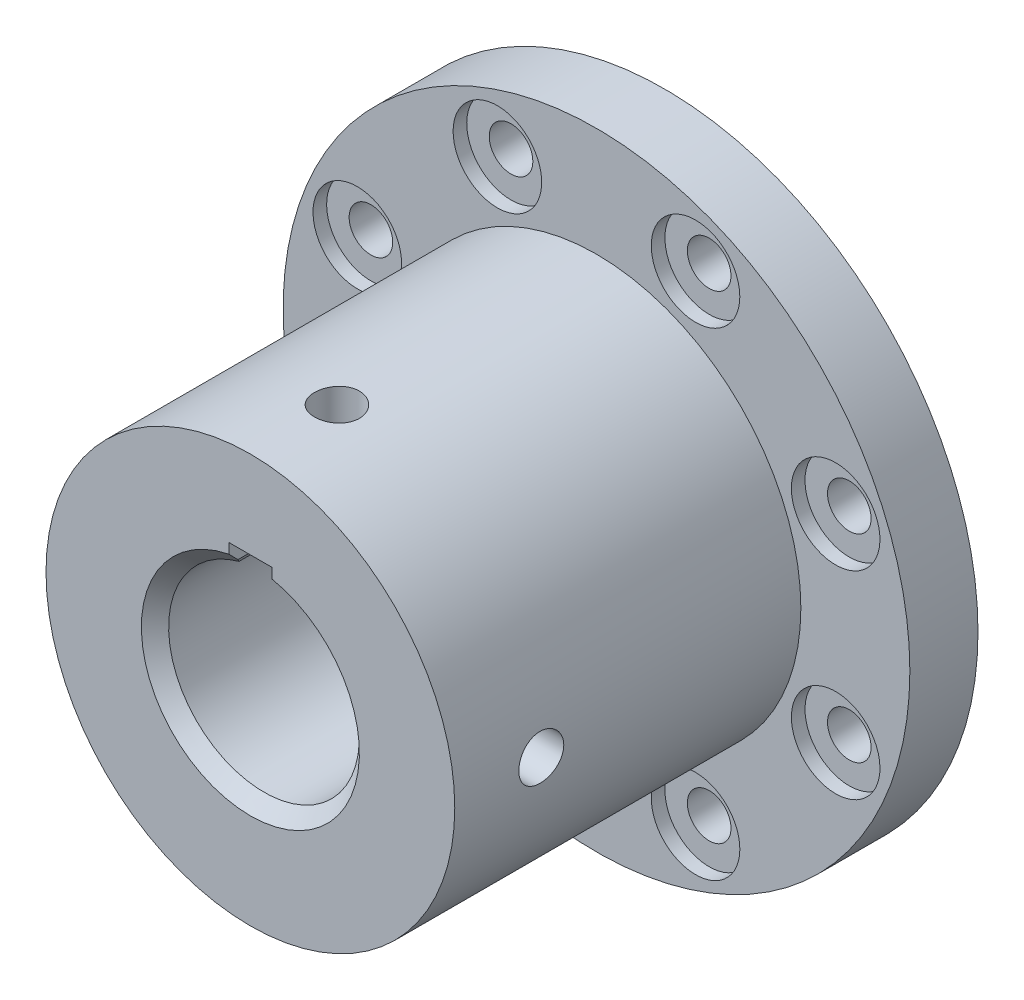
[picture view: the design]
ISO-10303-21;
HEADER;
FILE_DESCRIPTION(('STEP AP214'),'2;1');
FILE_NAME('part.step','',(''),(''),'','','');
FILE_SCHEMA(('AUTOMOTIVE_DESIGN { 1 0 10303 214 1 1 1 1 }'));
ENDSEC;
DATA;
#1=APPLICATION_CONTEXT('core data for automotive mechanical design processes');
#2=APPLICATION_PROTOCOL_DEFINITION('international standard','automotive_design',2000,#1);
#3=PRODUCT_CONTEXT('',#1,'mechanical');
#4=PRODUCT('Part','Part','',(#3));
#5=PRODUCT_RELATED_PRODUCT_CATEGORY('part','',(#4));
#6=PRODUCT_DEFINITION_FORMATION('','',#4);
#7=PRODUCT_DEFINITION_CONTEXT('part definition',#1,'design');
#8=PRODUCT_DEFINITION('design','',#6,#7);
#9=PRODUCT_DEFINITION_SHAPE('','',#8);
#10=(LENGTH_UNIT() NAMED_UNIT(*) SI_UNIT(.MILLI.,.METRE.));
#11=(NAMED_UNIT(*) PLANE_ANGLE_UNIT() SI_UNIT($,.RADIAN.));
#12=(NAMED_UNIT(*) SI_UNIT($,.STERADIAN.) SOLID_ANGLE_UNIT());
#13=UNCERTAINTY_MEASURE_WITH_UNIT(LENGTH_MEASURE(1.E-05),#10,'distance_accuracy_value','');
#14=(GEOMETRIC_REPRESENTATION_CONTEXT(3) GLOBAL_UNCERTAINTY_ASSIGNED_CONTEXT((#13)) GLOBAL_UNIT_ASSIGNED_CONTEXT((#10,
#11,#12)) REPRESENTATION_CONTEXT('',''));
#15=CARTESIAN_POINT('',(0.,0.,0.));
#16=DIRECTION('',(0.,0.,1.));
#17=DIRECTION('',(1.,0.,0.));
#18=AXIS2_PLACEMENT_3D('',#15,#16,#17);
#19=CARTESIAN_POINT('',(0.,0.,5.));
#20=DIRECTION('',(0.,0.,1.));
#21=DIRECTION('',(1.,0.,0.));
#22=AXIS2_PLACEMENT_3D('',#19,#20,#21);
#23=PLANE('',#22);
#24=CARTESIAN_POINT('',(-7.27197040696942,17.5533030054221,5.));
#25=DIRECTION('',(0.,0.,1.));
#26=DIRECTION('',(0.707106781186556,0.707106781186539,0.));
#27=AXIS2_PLACEMENT_3D('',#24,#25,#26);
#28=CIRCLE('',#27,3.25);
#29=CARTESIAN_POINT('',(-4.97387336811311,19.8514000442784,5.));
#30=VERTEX_POINT('',#29);
#31=EDGE_CURVE('E416',#30,#30,#28,.T.);
#32=ORIENTED_EDGE('',*,*,#31,.F.);
#33=EDGE_LOOP('',(#32));
#34=FACE_BOUND('',#33,.T.);
#35=CARTESIAN_POINT('',(-17.5541191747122,7.27000000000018,5.));
#36=DIRECTION('',(0.,0.,1.));
#37=DIRECTION('',(0.,1.,0.));
#38=AXIS2_PLACEMENT_3D('',#35,#36,#37);
#39=CIRCLE('',#38,3.25);
#40=CARTESIAN_POINT('',(-17.5541191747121,10.5200000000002,5.));
#41=VERTEX_POINT('',#40);
#42=EDGE_CURVE('E420',#41,#41,#39,.T.);
#43=ORIENTED_EDGE('',*,*,#42,.F.);
#44=EDGE_LOOP('',(#43));
#45=FACE_BOUND('',#44,.T.);
#46=CARTESIAN_POINT('',(-17.5533030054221,-7.27197040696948,5.));
#47=DIRECTION('',(0.,0.,1.));
#48=DIRECTION('',(-0.707106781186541,0.707106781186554,0.));
#49=AXIS2_PLACEMENT_3D('',#46,#47,#48);
#50=CIRCLE('',#49,3.25);
#51=CARTESIAN_POINT('',(-19.8514000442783,-4.97387336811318,5.));
#52=VERTEX_POINT('',#51);
#53=EDGE_CURVE('E424',#52,#52,#50,.T.);
#54=ORIENTED_EDGE('',*,*,#53,.F.);
#55=EDGE_LOOP('',(#54));
#56=FACE_BOUND('',#55,.T.);
#57=CARTESIAN_POINT('',(-7.27,-17.5541191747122,5.));
#58=DIRECTION('',(0.,0.,1.));
#59=DIRECTION('',(-1.,0.,0.));
#60=AXIS2_PLACEMENT_3D('',#57,#58,#59);
#61=CIRCLE('',#60,3.25);
#62=CARTESIAN_POINT('',(-10.52,-17.5541191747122,5.));
#63=VERTEX_POINT('',#62);
#64=EDGE_CURVE('E428',#63,#63,#61,.T.);
#65=ORIENTED_EDGE('',*,*,#64,.F.);
#66=EDGE_LOOP('',(#65));
#67=FACE_BOUND('',#66,.T.);
#68=CARTESIAN_POINT('',(7.27197040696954,-17.5533030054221,5.));
#69=DIRECTION('',(0.,0.,1.));
#70=DIRECTION('',(-0.707106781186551,-0.707106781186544,0.));
#71=AXIS2_PLACEMENT_3D('',#68,#69,#70);
#72=CIRCLE('',#71,3.25);
#73=CARTESIAN_POINT('',(4.97387336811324,-19.8514000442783,5.));
#74=VERTEX_POINT('',#73);
#75=EDGE_CURVE('E432',#74,#74,#72,.T.);
#76=ORIENTED_EDGE('',*,*,#75,.F.);
#77=EDGE_LOOP('',(#76));
#78=FACE_BOUND('',#77,.T.);
#79=CARTESIAN_POINT('',(17.5541191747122,-7.27000000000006,5.));
#80=DIRECTION('',(0.,0.,1.));
#81=DIRECTION('',(0.,-1.,0.));
#82=AXIS2_PLACEMENT_3D('',#79,#80,#81);
#83=CIRCLE('',#82,3.25);
#84=CARTESIAN_POINT('',(17.5541191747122,-10.5200000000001,5.));
#85=VERTEX_POINT('',#84);
#86=EDGE_CURVE('E436',#85,#85,#83,.T.);
#87=ORIENTED_EDGE('',*,*,#86,.F.);
#88=EDGE_LOOP('',(#87));
#89=FACE_BOUND('',#88,.T.);
#90=CARTESIAN_POINT('',(17.553303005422,7.2719704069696,5.));
#91=DIRECTION('',(0.,0.,1.));
#92=DIRECTION('',(0.707106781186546,-0.707106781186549,0.));
#93=AXIS2_PLACEMENT_3D('',#90,#91,#92);
#94=CIRCLE('',#93,3.25);
#95=CARTESIAN_POINT('',(19.8514000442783,4.97387336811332,5.));
#96=VERTEX_POINT('',#95);
#97=EDGE_CURVE('E440',#96,#96,#94,.T.);
#98=ORIENTED_EDGE('',*,*,#97,.F.);
#99=EDGE_LOOP('',(#98));
#100=FACE_BOUND('',#99,.T.);
#101=CARTESIAN_POINT('',(7.27,17.5541191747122,5.));
#102=DIRECTION('',(0.,0.,1.));
#103=DIRECTION('',(1.,0.,0.));
#104=AXIS2_PLACEMENT_3D('',#101,#102,#103);
#105=CIRCLE('',#104,3.25);
#106=CARTESIAN_POINT('',(10.52,17.5541191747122,5.));
#107=VERTEX_POINT('',#106);
#108=EDGE_CURVE('E444',#107,#107,#105,.T.);
#109=ORIENTED_EDGE('',*,*,#108,.F.);
#110=EDGE_LOOP('',(#109));
#111=FACE_BOUND('',#110,.T.);
#112=CARTESIAN_POINT('',(0.,0.,5.));
#113=DIRECTION('',(0.,0.,1.));
#114=DIRECTION('',(1.,0.,0.));
#115=AXIS2_PLACEMENT_3D('',#112,#113,#114);
#116=CIRCLE('',#115,23.);
#117=CARTESIAN_POINT('',(23.,0.,5.));
#118=VERTEX_POINT('',#117);
#119=EDGE_CURVE('E448',#118,#118,#116,.T.);
#120=ORIENTED_EDGE('',*,*,#119,.T.);
#121=EDGE_LOOP('',(#120));
#122=FACE_BOUND('',#121,.T.);
#123=CARTESIAN_POINT('',(0.,0.,5.));
#124=DIRECTION('',(0.,0.,1.));
#125=DIRECTION('',(1.,0.,0.));
#126=AXIS2_PLACEMENT_3D('',#123,#124,#125);
#127=CIRCLE('',#126,15.);
#128=CARTESIAN_POINT('',(15.,0.,5.));
#129=VERTEX_POINT('',#128);
#130=EDGE_CURVE('E289',#129,#129,#127,.T.);
#131=ORIENTED_EDGE('',*,*,#130,.F.);
#132=EDGE_LOOP('',(#131));
#133=FACE_BOUND('',#132,.T.);
#134=ADVANCED_FACE('F34',(#34,#45,#56,#67,#78,#89,#100,#111,#122,#133),#23,.T.);
#135=CARTESIAN_POINT('',(-7.27197040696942,17.5533030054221,5.));
#136=DIRECTION('',(0.,0.,1.));
#137=DIRECTION('',(1.,0.,0.));
#138=AXIS2_PLACEMENT_3D('',#135,#136,#137);
#139=CYLINDRICAL_SURFACE('',#138,1.6);
#140=CARTESIAN_POINT('',(-7.27197040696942,17.5533030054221,0.));
#141=DIRECTION('',(0.,0.,1.));
#142=DIRECTION('',(1.,0.,0.));
#143=AXIS2_PLACEMENT_3D('',#140,#141,#142);
#144=CIRCLE('',#143,1.6);
#145=CARTESIAN_POINT('',(-5.67197040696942,17.5533030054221,0.));
#146=VERTEX_POINT('',#145);
#147=EDGE_CURVE('E489',#146,#146,#144,.T.);
#148=ORIENTED_EDGE('',*,*,#147,.F.);
#149=EDGE_LOOP('',(#148));
#150=FACE_BOUND('',#149,.T.);
#151=CARTESIAN_POINT('',(-7.27197040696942,17.5533030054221,4.));
#152=DIRECTION('',(0.,0.,1.));
#153=DIRECTION('',(1.,0.,0.));
#154=AXIS2_PLACEMENT_3D('',#151,#152,#153);
#155=CIRCLE('',#154,1.6);
#156=CARTESIAN_POINT('',(-5.67197040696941,17.5533030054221,4.));
#157=VERTEX_POINT('',#156);
#158=EDGE_CURVE('E457',#157,#157,#155,.F.);
#159=ORIENTED_EDGE('',*,*,#158,.F.);
#160=EDGE_LOOP('',(#159));
#161=FACE_BOUND('',#160,.T.);
#162=ADVANCED_FACE('F356',(#150,#161),#139,.F.);
#163=CARTESIAN_POINT('',(-17.5541191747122,7.27000000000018,5.));
#164=DIRECTION('',(0.,0.,1.));
#165=DIRECTION('',(1.,0.,0.));
#166=AXIS2_PLACEMENT_3D('',#163,#164,#165);
#167=CYLINDRICAL_SURFACE('',#166,1.6);
#168=CARTESIAN_POINT('',(-17.5541191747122,7.27000000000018,0.));
#169=DIRECTION('',(0.,0.,1.));
#170=DIRECTION('',(1.,0.,0.));
#171=AXIS2_PLACEMENT_3D('',#168,#169,#170);
#172=CIRCLE('',#171,1.6);
#173=CARTESIAN_POINT('',(-15.9541191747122,7.27000000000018,0.));
#174=VERTEX_POINT('',#173);
#175=EDGE_CURVE('E491',#174,#174,#172,.T.);
#176=ORIENTED_EDGE('',*,*,#175,.F.);
#177=EDGE_LOOP('',(#176));
#178=FACE_BOUND('',#177,.T.);
#179=CARTESIAN_POINT('',(-17.5541191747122,7.27000000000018,4.));
#180=DIRECTION('',(0.,0.,1.));
#181=DIRECTION('',(1.,0.,0.));
#182=AXIS2_PLACEMENT_3D('',#179,#180,#181);
#183=CIRCLE('',#182,1.6);
#184=CARTESIAN_POINT('',(-15.9541191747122,7.27000000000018,4.));
#185=VERTEX_POINT('',#184);
#186=EDGE_CURVE('E462',#185,#185,#183,.F.);
#187=ORIENTED_EDGE('',*,*,#186,.F.);
#188=EDGE_LOOP('',(#187));
#189=FACE_BOUND('',#188,.T.);
#190=ADVANCED_FACE('F359',(#178,#189),#167,.F.);
#191=CARTESIAN_POINT('',(-17.5533030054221,-7.27197040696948,5.));
#192=DIRECTION('',(0.,0.,1.));
#193=DIRECTION('',(1.,0.,0.));
#194=AXIS2_PLACEMENT_3D('',#191,#192,#193);
#195=CYLINDRICAL_SURFACE('',#194,1.6);
#196=CARTESIAN_POINT('',(-17.5533030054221,-7.27197040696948,0.));
#197=DIRECTION('',(0.,0.,1.));
#198=DIRECTION('',(1.,0.,0.));
#199=AXIS2_PLACEMENT_3D('',#196,#197,#198);
#200=CIRCLE('',#199,1.6);
#201=CARTESIAN_POINT('',(-15.9533030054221,-7.27197040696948,0.));
#202=VERTEX_POINT('',#201);
#203=EDGE_CURVE('E494',#202,#202,#200,.T.);
#204=ORIENTED_EDGE('',*,*,#203,.F.);
#205=EDGE_LOOP('',(#204));
#206=FACE_BOUND('',#205,.T.);
#207=CARTESIAN_POINT('',(-17.5533030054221,-7.27197040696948,4.));
#208=DIRECTION('',(0.,0.,1.));
#209=DIRECTION('',(1.,0.,0.));
#210=AXIS2_PLACEMENT_3D('',#207,#208,#209);
#211=CIRCLE('',#210,1.6);
#212=CARTESIAN_POINT('',(-15.9533030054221,-7.27197040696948,4.));
#213=VERTEX_POINT('',#212);
#214=EDGE_CURVE('E467',#213,#213,#211,.F.);
#215=ORIENTED_EDGE('',*,*,#214,.F.);
#216=EDGE_LOOP('',(#215));
#217=FACE_BOUND('',#216,.T.);
#218=ADVANCED_FACE('F363',(#206,#217),#195,.F.);
#219=CARTESIAN_POINT('',(-7.27,-17.5541191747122,5.));
#220=DIRECTION('',(0.,0.,1.));
#221=DIRECTION('',(1.,0.,0.));
#222=AXIS2_PLACEMENT_3D('',#219,#220,#221);
#223=CYLINDRICAL_SURFACE('',#222,1.6);
#224=CARTESIAN_POINT('',(-7.27,-17.5541191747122,0.));
#225=DIRECTION('',(0.,0.,1.));
#226=DIRECTION('',(1.,0.,0.));
#227=AXIS2_PLACEMENT_3D('',#224,#225,#226);
#228=CIRCLE('',#227,1.6);
#229=CARTESIAN_POINT('',(-5.67,-17.5541191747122,0.));
#230=VERTEX_POINT('',#229);
#231=EDGE_CURVE('E497',#230,#230,#228,.T.);
#232=ORIENTED_EDGE('',*,*,#231,.F.);
#233=EDGE_LOOP('',(#232));
#234=FACE_BOUND('',#233,.T.);
#235=CARTESIAN_POINT('',(-7.27,-17.5541191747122,4.));
#236=DIRECTION('',(0.,0.,1.));
#237=DIRECTION('',(1.,0.,0.));
#238=AXIS2_PLACEMENT_3D('',#235,#236,#237);
#239=CIRCLE('',#238,1.6);
#240=CARTESIAN_POINT('',(-5.67,-17.5541191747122,4.));
#241=VERTEX_POINT('',#240);
#242=EDGE_CURVE('E472',#241,#241,#239,.F.);
#243=ORIENTED_EDGE('',*,*,#242,.F.);
#244=EDGE_LOOP('',(#243));
#245=FACE_BOUND('',#244,.T.);
#246=ADVANCED_FACE('F367',(#234,#245),#223,.F.);
#247=CARTESIAN_POINT('',(7.27197040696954,-17.5533030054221,5.));
#248=DIRECTION('',(0.,0.,1.));
#249=DIRECTION('',(1.,0.,0.));
#250=AXIS2_PLACEMENT_3D('',#247,#248,#249);
#251=CYLINDRICAL_SURFACE('',#250,1.6);
#252=CARTESIAN_POINT('',(7.27197040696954,-17.5533030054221,0.));
#253=DIRECTION('',(0.,0.,1.));
#254=DIRECTION('',(1.,0.,0.));
#255=AXIS2_PLACEMENT_3D('',#252,#253,#254);
#256=CIRCLE('',#255,1.6);
#257=CARTESIAN_POINT('',(8.87197040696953,-17.5533030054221,0.));
#258=VERTEX_POINT('',#257);
#259=EDGE_CURVE('E500',#258,#258,#256,.T.);
#260=ORIENTED_EDGE('',*,*,#259,.F.);
#261=EDGE_LOOP('',(#260));
#262=FACE_BOUND('',#261,.T.);
#263=CARTESIAN_POINT('',(7.27197040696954,-17.5533030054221,4.));
#264=DIRECTION('',(0.,0.,1.));
#265=DIRECTION('',(1.,0.,0.));
#266=AXIS2_PLACEMENT_3D('',#263,#264,#265);
#267=CIRCLE('',#266,1.6);
#268=CARTESIAN_POINT('',(8.87197040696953,-17.5533030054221,4.));
#269=VERTEX_POINT('',#268);
#270=EDGE_CURVE('E477',#269,#269,#267,.F.);
#271=ORIENTED_EDGE('',*,*,#270,.F.);
#272=EDGE_LOOP('',(#271));
#273=FACE_BOUND('',#272,.T.);
#274=ADVANCED_FACE('F371',(#262,#273),#251,.F.);
#275=CARTESIAN_POINT('',(17.5541191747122,-7.27000000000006,5.));
#276=DIRECTION('',(0.,0.,1.));
#277=DIRECTION('',(1.,0.,0.));
#278=AXIS2_PLACEMENT_3D('',#275,#276,#277);
#279=CYLINDRICAL_SURFACE('',#278,1.6);
#280=CARTESIAN_POINT('',(17.5541191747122,-7.27000000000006,0.));
#281=DIRECTION('',(0.,0.,1.));
#282=DIRECTION('',(1.,0.,0.));
#283=AXIS2_PLACEMENT_3D('',#280,#281,#282);
#284=CIRCLE('',#283,1.6);
#285=CARTESIAN_POINT('',(19.1541191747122,-7.27000000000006,0.));
#286=VERTEX_POINT('',#285);
#287=EDGE_CURVE('E503',#286,#286,#284,.T.);
#288=ORIENTED_EDGE('',*,*,#287,.F.);
#289=EDGE_LOOP('',(#288));
#290=FACE_BOUND('',#289,.T.);
#291=CARTESIAN_POINT('',(17.5541191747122,-7.27000000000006,4.));
#292=DIRECTION('',(0.,0.,1.));
#293=DIRECTION('',(1.,0.,0.));
#294=AXIS2_PLACEMENT_3D('',#291,#292,#293);
#295=CIRCLE('',#294,1.6);
#296=CARTESIAN_POINT('',(19.1541191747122,-7.27000000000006,4.));
#297=VERTEX_POINT('',#296);
#298=EDGE_CURVE('E482',#297,#297,#295,.F.);
#299=ORIENTED_EDGE('',*,*,#298,.F.);
#300=EDGE_LOOP('',(#299));
#301=FACE_BOUND('',#300,.T.);
#302=ADVANCED_FACE('F375',(#290,#301),#279,.F.);
#303=CARTESIAN_POINT('',(17.553303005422,7.2719704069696,5.));
#304=DIRECTION('',(0.,0.,1.));
#305=DIRECTION('',(1.,0.,0.));
#306=AXIS2_PLACEMENT_3D('',#303,#304,#305);
#307=CYLINDRICAL_SURFACE('',#306,1.6);
#308=CARTESIAN_POINT('',(17.553303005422,7.2719704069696,0.));
#309=DIRECTION('',(0.,0.,1.));
#310=DIRECTION('',(1.,0.,0.));
#311=AXIS2_PLACEMENT_3D('',#308,#309,#310);
#312=CIRCLE('',#311,1.6);
#313=CARTESIAN_POINT('',(19.153303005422,7.2719704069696,0.));
#314=VERTEX_POINT('',#313);
#315=EDGE_CURVE('E506',#314,#314,#312,.T.);
#316=ORIENTED_EDGE('',*,*,#315,.F.);
#317=EDGE_LOOP('',(#316));
#318=FACE_BOUND('',#317,.T.);
#319=CARTESIAN_POINT('',(17.553303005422,7.2719704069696,4.));
#320=DIRECTION('',(0.,0.,1.));
#321=DIRECTION('',(1.,0.,0.));
#322=AXIS2_PLACEMENT_3D('',#319,#320,#321);
#323=CIRCLE('',#322,1.6);
#324=CARTESIAN_POINT('',(19.153303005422,7.2719704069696,4.));
#325=VERTEX_POINT('',#324);
#326=EDGE_CURVE('E487',#325,#325,#323,.F.);
#327=ORIENTED_EDGE('',*,*,#326,.F.);
#328=EDGE_LOOP('',(#327));
#329=FACE_BOUND('',#328,.T.);
#330=ADVANCED_FACE('F379',(#318,#329),#307,.F.);
#331=CARTESIAN_POINT('',(7.27,17.5541191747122,5.));
#332=DIRECTION('',(0.,0.,1.));
#333=DIRECTION('',(1.,0.,0.));
#334=AXIS2_PLACEMENT_3D('',#331,#332,#333);
#335=CYLINDRICAL_SURFACE('',#334,1.6);
#336=CARTESIAN_POINT('',(7.27,17.5541191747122,0.));
#337=DIRECTION('',(0.,0.,1.));
#338=DIRECTION('',(1.,0.,0.));
#339=AXIS2_PLACEMENT_3D('',#336,#337,#338);
#340=CIRCLE('',#339,1.6);
#341=CARTESIAN_POINT('',(8.87,17.5541191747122,0.));
#342=VERTEX_POINT('',#341);
#343=EDGE_CURVE('E514',#342,#342,#340,.T.);
#344=ORIENTED_EDGE('',*,*,#343,.F.);
#345=EDGE_LOOP('',(#344));
#346=FACE_BOUND('',#345,.T.);
#347=CARTESIAN_POINT('',(7.27,17.5541191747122,4.));
#348=DIRECTION('',(0.,0.,1.));
#349=DIRECTION('',(1.,0.,0.));
#350=AXIS2_PLACEMENT_3D('',#347,#348,#349);
#351=CIRCLE('',#350,1.6);
#352=CARTESIAN_POINT('',(8.87,17.5541191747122,4.));
#353=VERTEX_POINT('',#352);
#354=EDGE_CURVE('E512',#353,#353,#351,.F.);
#355=ORIENTED_EDGE('',*,*,#354,.F.);
#356=EDGE_LOOP('',(#355));
#357=FACE_BOUND('',#356,.T.);
#358=ADVANCED_FACE('F383',(#346,#357),#335,.F.);
#359=CARTESIAN_POINT('',(0.,0.,5.));
#360=DIRECTION('',(0.,0.,-1.));
#361=DIRECTION('',(-1.,0.,0.));
#362=AXIS2_PLACEMENT_3D('',#359,#360,#361);
#363=CYLINDRICAL_SURFACE('',#362,23.);
#364=ORIENTED_EDGE('',*,*,#119,.F.);
#365=EDGE_LOOP('',(#364));
#366=FACE_BOUND('',#365,.T.);
#367=CARTESIAN_POINT('',(0.,0.,0.));
#368=DIRECTION('',(0.,0.,1.));
#369=DIRECTION('',(1.,0.,0.));
#370=AXIS2_PLACEMENT_3D('',#367,#368,#369);
#371=CIRCLE('',#370,23.);
#372=CARTESIAN_POINT('',(23.,0.,0.));
#373=VERTEX_POINT('',#372);
#374=EDGE_CURVE('E521',#373,#373,#371,.T.);
#375=ORIENTED_EDGE('',*,*,#374,.T.);
#376=EDGE_LOOP('',(#375));
#377=FACE_BOUND('',#376,.T.);
#378=ADVANCED_FACE('F218',(#366,#377),#363,.T.);
#379=CARTESIAN_POINT('',(0.,0.,5.));
#380=DIRECTION('',(0.,0.,1.));
#381=DIRECTION('',(1.,0.,0.));
#382=AXIS2_PLACEMENT_3D('',#379,#380,#381);
#383=CIRCLE('',#382,7.);
#384=CARTESIAN_POINT('',(7.,0.,5.));
#385=VERTEX_POINT('',#384);
#386=EDGE_CURVE('E525',#385,#385,#383,.F.);
#387=ORIENTED_EDGE('',*,*,#386,.F.);
#388=EDGE_LOOP('',(#387));
#389=FACE_BOUND('',#388,.T.);
#390=CARTESIAN_POINT('',(0.,0.,5.));
#391=DIRECTION('',(0.,0.,1.));
#392=DIRECTION('',(1.,0.,0.));
#393=AXIS2_PLACEMENT_3D('',#390,#391,#392);
#394=CIRCLE('',#393,2.);
#395=CARTESIAN_POINT('',(2.,0.,5.));
#396=VERTEX_POINT('',#395);
#397=EDGE_CURVE('E517',#396,#396,#394,.T.);
#398=ORIENTED_EDGE('',*,*,#397,.F.);
#399=EDGE_LOOP('',(#398));
#400=FACE_BOUND('',#399,.T.);
#401=ADVANCED_FACE('F400',(#389,#400),#23,.T.);
#402=CARTESIAN_POINT('',(0.,0.,0.));
#403=DIRECTION('',(0.,0.,1.));
#404=DIRECTION('',(1.,0.,0.));
#405=AXIS2_PLACEMENT_3D('',#402,#403,#404);
#406=PLANE('',#405);
#407=ORIENTED_EDGE('',*,*,#147,.T.);
#408=EDGE_LOOP('',(#407));
#409=FACE_BOUND('',#408,.T.);
#410=ORIENTED_EDGE('',*,*,#175,.T.);
#411=EDGE_LOOP('',(#410));
#412=FACE_BOUND('',#411,.T.);
#413=ORIENTED_EDGE('',*,*,#203,.T.);
#414=EDGE_LOOP('',(#413));
#415=FACE_BOUND('',#414,.T.);
#416=ORIENTED_EDGE('',*,*,#231,.T.);
#417=EDGE_LOOP('',(#416));
#418=FACE_BOUND('',#417,.T.);
#419=ORIENTED_EDGE('',*,*,#259,.T.);
#420=EDGE_LOOP('',(#419));
#421=FACE_BOUND('',#420,.T.);
#422=ORIENTED_EDGE('',*,*,#287,.T.);
#423=EDGE_LOOP('',(#422));
#424=FACE_BOUND('',#423,.T.);
#425=ORIENTED_EDGE('',*,*,#315,.T.);
#426=EDGE_LOOP('',(#425));
#427=FACE_BOUND('',#426,.T.);
#428=ORIENTED_EDGE('',*,*,#343,.T.);
#429=EDGE_LOOP('',(#428));
#430=FACE_BOUND('',#429,.T.);
#431=CARTESIAN_POINT('',(0.,0.,0.));
#432=DIRECTION('',(0.,0.,1.));
#433=DIRECTION('',(1.,0.,0.));
#434=AXIS2_PLACEMENT_3D('',#431,#432,#433);
#435=CIRCLE('',#434,2.);
#436=CARTESIAN_POINT('',(2.,0.,0.));
#437=VERTEX_POINT('',#436);
#438=EDGE_CURVE('E518',#437,#437,#435,.T.);
#439=ORIENTED_EDGE('',*,*,#438,.T.);
#440=EDGE_LOOP('',(#439));
#441=FACE_BOUND('',#440,.T.);
#442=ORIENTED_EDGE('',*,*,#374,.F.);
#443=EDGE_LOOP('',(#442));
#444=FACE_BOUND('',#443,.T.);
#445=ADVANCED_FACE('F398',(#409,#412,#415,#418,#421,#424,#427,#430,#441,#444),#406,.F.);
#446=CARTESIAN_POINT('',(0.,0.,0.));
#447=DIRECTION('',(0.,0.,1.));
#448=DIRECTION('',(1.,0.,0.));
#449=AXIS2_PLACEMENT_3D('',#446,#447,#448);
#450=CYLINDRICAL_SURFACE('',#449,2.);
#451=ORIENTED_EDGE('',*,*,#438,.F.);
#452=EDGE_LOOP('',(#451));
#453=FACE_BOUND('',#452,.T.);
#454=ORIENTED_EDGE('',*,*,#397,.T.);
#455=EDGE_LOOP('',(#454));
#456=FACE_BOUND('',#455,.T.);
#457=ADVANCED_FACE('F388',(#453,#456),#450,.F.);
#458=CARTESIAN_POINT('',(7.27,17.5541191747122,4.));
#459=DIRECTION('',(0.,0.,1.));
#460=DIRECTION('',(1.,0.,0.));
#461=AXIS2_PLACEMENT_3D('',#458,#459,#460);
#462=PLANE('',#461);
#463=CARTESIAN_POINT('',(7.27,17.5541191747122,4.));
#464=DIRECTION('',(0.,0.,1.));
#465=DIRECTION('',(1.,0.,0.));
#466=AXIS2_PLACEMENT_3D('',#463,#464,#465);
#467=CIRCLE('',#466,3.25);
#468=CARTESIAN_POINT('',(10.52,17.5541191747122,4.));
#469=VERTEX_POINT('',#468);
#470=EDGE_CURVE('E509',#469,#469,#467,.T.);
#471=ORIENTED_EDGE('',*,*,#470,.T.);
#472=EDGE_LOOP('',(#471));
#473=FACE_BOUND('',#472,.T.);
#474=ORIENTED_EDGE('',*,*,#354,.T.);
#475=EDGE_LOOP('',(#474));
#476=FACE_BOUND('',#475,.T.);
#477=ADVANCED_FACE('F385',(#473,#476),#462,.T.);
#478=CARTESIAN_POINT('',(7.27,17.5541191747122,4.));
#479=DIRECTION('',(0.,0.,1.));
#480=DIRECTION('',(1.,0.,0.));
#481=AXIS2_PLACEMENT_3D('',#478,#479,#480);
#482=CYLINDRICAL_SURFACE('',#481,3.25);
#483=ORIENTED_EDGE('',*,*,#470,.F.);
#484=EDGE_LOOP('',(#483));
#485=FACE_BOUND('',#484,.T.);
#486=ORIENTED_EDGE('',*,*,#108,.T.);
#487=EDGE_LOOP('',(#486));
#488=FACE_BOUND('',#487,.T.);
#489=ADVANCED_FACE('F351',(#485,#488),#482,.F.);
#490=CARTESIAN_POINT('',(17.553303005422,7.2719704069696,4.));
#491=DIRECTION('',(0.,0.,1.));
#492=DIRECTION('',(0.707106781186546,-0.707106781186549,0.));
#493=AXIS2_PLACEMENT_3D('',#490,#491,#492);
#494=PLANE('',#493);
#495=CARTESIAN_POINT('',(17.553303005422,7.2719704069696,4.));
#496=DIRECTION('',(0.,0.,1.));
#497=DIRECTION('',(0.707106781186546,-0.707106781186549,0.));
#498=AXIS2_PLACEMENT_3D('',#495,#496,#497);
#499=CIRCLE('',#498,3.25);
#500=CARTESIAN_POINT('',(19.8514000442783,4.97387336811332,4.));
#501=VERTEX_POINT('',#500);
#502=EDGE_CURVE('E484',#501,#501,#499,.T.);
#503=ORIENTED_EDGE('',*,*,#502,.T.);
#504=EDGE_LOOP('',(#503));
#505=FACE_BOUND('',#504,.T.);
#506=ORIENTED_EDGE('',*,*,#326,.T.);
#507=EDGE_LOOP('',(#506));
#508=FACE_BOUND('',#507,.T.);
#509=ADVANCED_FACE('F348',(#505,#508),#494,.T.);
#510=CARTESIAN_POINT('',(17.553303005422,7.2719704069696,4.));
#511=DIRECTION('',(0.,0.,1.));
#512=DIRECTION('',(1.,0.,0.));
#513=AXIS2_PLACEMENT_3D('',#510,#511,#512);
#514=CYLINDRICAL_SURFACE('',#513,3.25);
#515=ORIENTED_EDGE('',*,*,#502,.F.);
#516=EDGE_LOOP('',(#515));
#517=FACE_BOUND('',#516,.T.);
#518=ORIENTED_EDGE('',*,*,#97,.T.);
#519=EDGE_LOOP('',(#518));
#520=FACE_BOUND('',#519,.T.);
#521=ADVANCED_FACE('F343',(#517,#520),#514,.F.);
#522=CARTESIAN_POINT('',(17.5541191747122,-7.27000000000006,4.));
#523=DIRECTION('',(0.,0.,1.));
#524=DIRECTION('',(0.,-1.,0.));
#525=AXIS2_PLACEMENT_3D('',#522,#523,#524);
#526=PLANE('',#525);
#527=CARTESIAN_POINT('',(17.5541191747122,-7.27000000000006,4.));
#528=DIRECTION('',(0.,0.,1.));
#529=DIRECTION('',(0.,-1.,0.));
#530=AXIS2_PLACEMENT_3D('',#527,#528,#529);
#531=CIRCLE('',#530,3.25);
#532=CARTESIAN_POINT('',(17.5541191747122,-10.5200000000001,4.));
#533=VERTEX_POINT('',#532);
#534=EDGE_CURVE('E479',#533,#533,#531,.T.);
#535=ORIENTED_EDGE('',*,*,#534,.T.);
#536=EDGE_LOOP('',(#535));
#537=FACE_BOUND('',#536,.T.);
#538=ORIENTED_EDGE('',*,*,#298,.T.);
#539=EDGE_LOOP('',(#538));
#540=FACE_BOUND('',#539,.T.);
#541=ADVANCED_FACE('F340',(#537,#540),#526,.T.);
#542=CARTESIAN_POINT('',(17.5541191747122,-7.27000000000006,4.));
#543=DIRECTION('',(0.,0.,1.));
#544=DIRECTION('',(1.,0.,0.));
#545=AXIS2_PLACEMENT_3D('',#542,#543,#544);
#546=CYLINDRICAL_SURFACE('',#545,3.25);
#547=ORIENTED_EDGE('',*,*,#534,.F.);
#548=EDGE_LOOP('',(#547));
#549=FACE_BOUND('',#548,.T.);
#550=ORIENTED_EDGE('',*,*,#86,.T.);
#551=EDGE_LOOP('',(#550));
#552=FACE_BOUND('',#551,.T.);
#553=ADVANCED_FACE('F335',(#549,#552),#546,.F.);
#554=CARTESIAN_POINT('',(7.27197040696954,-17.5533030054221,4.));
#555=DIRECTION('',(0.,0.,1.));
#556=DIRECTION('',(-0.707106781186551,-0.707106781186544,0.));
#557=AXIS2_PLACEMENT_3D('',#554,#555,#556);
#558=PLANE('',#557);
#559=CARTESIAN_POINT('',(7.27197040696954,-17.5533030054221,4.));
#560=DIRECTION('',(0.,0.,1.));
#561=DIRECTION('',(-0.707106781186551,-0.707106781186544,0.));
#562=AXIS2_PLACEMENT_3D('',#559,#560,#561);
#563=CIRCLE('',#562,3.25);
#564=CARTESIAN_POINT('',(4.97387336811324,-19.8514000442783,4.));
#565=VERTEX_POINT('',#564);
#566=EDGE_CURVE('E474',#565,#565,#563,.T.);
#567=ORIENTED_EDGE('',*,*,#566,.T.);
#568=EDGE_LOOP('',(#567));
#569=FACE_BOUND('',#568,.T.);
#570=ORIENTED_EDGE('',*,*,#270,.T.);
#571=EDGE_LOOP('',(#570));
#572=FACE_BOUND('',#571,.T.);
#573=ADVANCED_FACE('F332',(#569,#572),#558,.T.);
#574=CARTESIAN_POINT('',(7.27197040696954,-17.5533030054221,4.));
#575=DIRECTION('',(0.,0.,1.));
#576=DIRECTION('',(1.,0.,0.));
#577=AXIS2_PLACEMENT_3D('',#574,#575,#576);
#578=CYLINDRICAL_SURFACE('',#577,3.25);
#579=ORIENTED_EDGE('',*,*,#566,.F.);
#580=EDGE_LOOP('',(#579));
#581=FACE_BOUND('',#580,.T.);
#582=ORIENTED_EDGE('',*,*,#75,.T.);
#583=EDGE_LOOP('',(#582));
#584=FACE_BOUND('',#583,.T.);
#585=ADVANCED_FACE('F327',(#581,#584),#578,.F.);
#586=CARTESIAN_POINT('',(-7.27,-17.5541191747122,4.));
#587=DIRECTION('',(0.,0.,1.));
#588=DIRECTION('',(-1.,0.,0.));
#589=AXIS2_PLACEMENT_3D('',#586,#587,#588);
#590=PLANE('',#589);
#591=CARTESIAN_POINT('',(-7.27,-17.5541191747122,4.));
#592=DIRECTION('',(0.,0.,1.));
#593=DIRECTION('',(-1.,0.,0.));
#594=AXIS2_PLACEMENT_3D('',#591,#592,#593);
#595=CIRCLE('',#594,3.25);
#596=CARTESIAN_POINT('',(-10.52,-17.5541191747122,4.));
#597=VERTEX_POINT('',#596);
#598=EDGE_CURVE('E469',#597,#597,#595,.T.);
#599=ORIENTED_EDGE('',*,*,#598,.T.);
#600=EDGE_LOOP('',(#599));
#601=FACE_BOUND('',#600,.T.);
#602=ORIENTED_EDGE('',*,*,#242,.T.);
#603=EDGE_LOOP('',(#602));
#604=FACE_BOUND('',#603,.T.);
#605=ADVANCED_FACE('F324',(#601,#604),#590,.T.);
#606=CARTESIAN_POINT('',(-7.27,-17.5541191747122,4.));
#607=DIRECTION('',(0.,0.,1.));
#608=DIRECTION('',(1.,0.,0.));
#609=AXIS2_PLACEMENT_3D('',#606,#607,#608);
#610=CYLINDRICAL_SURFACE('',#609,3.25);
#611=ORIENTED_EDGE('',*,*,#598,.F.);
#612=EDGE_LOOP('',(#611));
#613=FACE_BOUND('',#612,.T.);
#614=ORIENTED_EDGE('',*,*,#64,.T.);
#615=EDGE_LOOP('',(#614));
#616=FACE_BOUND('',#615,.T.);
#617=ADVANCED_FACE('F319',(#613,#616),#610,.F.);
#618=CARTESIAN_POINT('',(-17.5533030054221,-7.27197040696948,4.));
#619=DIRECTION('',(0.,0.,1.));
#620=DIRECTION('',(-0.707106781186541,0.707106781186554,0.));
#621=AXIS2_PLACEMENT_3D('',#618,#619,#620);
#622=PLANE('',#621);
#623=CARTESIAN_POINT('',(-17.5533030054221,-7.27197040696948,4.));
#624=DIRECTION('',(0.,0.,1.));
#625=DIRECTION('',(-0.707106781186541,0.707106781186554,0.));
#626=AXIS2_PLACEMENT_3D('',#623,#624,#625);
#627=CIRCLE('',#626,3.25);
#628=CARTESIAN_POINT('',(-19.8514000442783,-4.97387336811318,4.));
#629=VERTEX_POINT('',#628);
#630=EDGE_CURVE('E464',#629,#629,#627,.T.);
#631=ORIENTED_EDGE('',*,*,#630,.T.);
#632=EDGE_LOOP('',(#631));
#633=FACE_BOUND('',#632,.T.);
#634=ORIENTED_EDGE('',*,*,#214,.T.);
#635=EDGE_LOOP('',(#634));
#636=FACE_BOUND('',#635,.T.);
#637=ADVANCED_FACE('F316',(#633,#636),#622,.T.);
#638=CARTESIAN_POINT('',(-17.5533030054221,-7.27197040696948,4.));
#639=DIRECTION('',(0.,0.,1.));
#640=DIRECTION('',(1.,0.,0.));
#641=AXIS2_PLACEMENT_3D('',#638,#639,#640);
#642=CYLINDRICAL_SURFACE('',#641,3.25);
#643=ORIENTED_EDGE('',*,*,#630,.F.);
#644=EDGE_LOOP('',(#643));
#645=FACE_BOUND('',#644,.T.);
#646=ORIENTED_EDGE('',*,*,#53,.T.);
#647=EDGE_LOOP('',(#646));
#648=FACE_BOUND('',#647,.T.);
#649=ADVANCED_FACE('F311',(#645,#648),#642,.F.);
#650=CARTESIAN_POINT('',(-17.5541191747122,7.27000000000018,4.));
#651=DIRECTION('',(0.,0.,1.));
#652=DIRECTION('',(0.,1.,0.));
#653=AXIS2_PLACEMENT_3D('',#650,#651,#652);
#654=PLANE('',#653);
#655=CARTESIAN_POINT('',(-17.5541191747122,7.27000000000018,4.));
#656=DIRECTION('',(0.,0.,1.));
#657=DIRECTION('',(0.,1.,0.));
#658=AXIS2_PLACEMENT_3D('',#655,#656,#657);
#659=CIRCLE('',#658,3.25);
#660=CARTESIAN_POINT('',(-17.5541191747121,10.5200000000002,4.));
#661=VERTEX_POINT('',#660);
#662=EDGE_CURVE('E459',#661,#661,#659,.T.);
#663=ORIENTED_EDGE('',*,*,#662,.T.);
#664=EDGE_LOOP('',(#663));
#665=FACE_BOUND('',#664,.T.);
#666=ORIENTED_EDGE('',*,*,#186,.T.);
#667=EDGE_LOOP('',(#666));
#668=FACE_BOUND('',#667,.T.);
#669=ADVANCED_FACE('F308',(#665,#668),#654,.T.);
#670=CARTESIAN_POINT('',(-17.5541191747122,7.27000000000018,4.));
#671=DIRECTION('',(0.,0.,1.));
#672=DIRECTION('',(1.,0.,0.));
#673=AXIS2_PLACEMENT_3D('',#670,#671,#672);
#674=CYLINDRICAL_SURFACE('',#673,3.25);
#675=ORIENTED_EDGE('',*,*,#662,.F.);
#676=EDGE_LOOP('',(#675));
#677=FACE_BOUND('',#676,.T.);
#678=ORIENTED_EDGE('',*,*,#42,.T.);
#679=EDGE_LOOP('',(#678));
#680=FACE_BOUND('',#679,.T.);
#681=ADVANCED_FACE('F303',(#677,#680),#674,.F.);
#682=CARTESIAN_POINT('',(-7.27197040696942,17.5533030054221,4.));
#683=DIRECTION('',(0.,0.,1.));
#684=DIRECTION('',(0.707106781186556,0.707106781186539,0.));
#685=AXIS2_PLACEMENT_3D('',#682,#683,#684);
#686=PLANE('',#685);
#687=CARTESIAN_POINT('',(-7.27197040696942,17.5533030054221,4.));
#688=DIRECTION('',(0.,0.,1.));
#689=DIRECTION('',(0.707106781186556,0.707106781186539,0.));
#690=AXIS2_PLACEMENT_3D('',#687,#688,#689);
#691=CIRCLE('',#690,3.25);
#692=CARTESIAN_POINT('',(-4.97387336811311,19.8514000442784,4.));
#693=VERTEX_POINT('',#692);
#694=EDGE_CURVE('E454',#693,#693,#691,.T.);
#695=ORIENTED_EDGE('',*,*,#694,.T.);
#696=EDGE_LOOP('',(#695));
#697=FACE_BOUND('',#696,.T.);
#698=ORIENTED_EDGE('',*,*,#158,.T.);
#699=EDGE_LOOP('',(#698));
#700=FACE_BOUND('',#699,.T.);
#701=ADVANCED_FACE('F298',(#697,#700),#686,.T.);
#702=CARTESIAN_POINT('',(-7.27197040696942,17.5533030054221,4.));
#703=DIRECTION('',(0.,0.,1.));
#704=DIRECTION('',(1.,0.,0.));
#705=AXIS2_PLACEMENT_3D('',#702,#703,#704);
#706=CYLINDRICAL_SURFACE('',#705,3.25);
#707=ORIENTED_EDGE('',*,*,#694,.F.);
#708=EDGE_LOOP('',(#707));
#709=FACE_BOUND('',#708,.T.);
#710=ORIENTED_EDGE('',*,*,#31,.T.);
#711=EDGE_LOOP('',(#710));
#712=FACE_BOUND('',#711,.T.);
#713=ADVANCED_FACE('F302',(#709,#712),#706,.F.);
#714=CARTESIAN_POINT('',(0.,0.,30.4));
#715=DIRECTION('',(0.,0.,1.));
#716=DIRECTION('',(1.,0.,0.));
#717=AXIS2_PLACEMENT_3D('',#714,#715,#716);
#718=PLANE('',#717);
#719=DIRECTION('',(0.,1.,0.));
#720=VECTOR('',#719,1.);
#721=CARTESIAN_POINT('',(1.5875,0.,30.4));
#722=LINE('',#721,#720);
#723=CARTESIAN_POINT('',(1.5875,7.84090834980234,30.4));
#724=VERTEX_POINT('',#723);
#725=CARTESIAN_POINT('',(1.5875,8.5875,30.4));
#726=VERTEX_POINT('',#725);
#727=EDGE_CURVE('E247',#724,#726,#722,.T.);
#728=ORIENTED_EDGE('',*,*,#727,.F.);
#729=CARTESIAN_POINT('',(0.,0.,30.4));
#730=DIRECTION('',(0.,0.,1.));
#731=DIRECTION('',(1.,0.,0.));
#732=AXIS2_PLACEMENT_3D('',#729,#730,#731);
#733=CIRCLE('',#732,8.00000000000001);
#734=CARTESIAN_POINT('',(-1.5875,7.84090834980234,30.4));
#735=VERTEX_POINT('',#734);
#736=EDGE_CURVE('E206',#724,#735,#733,.F.);
#737=ORIENTED_EDGE('',*,*,#736,.T.);
#738=DIRECTION('',(0.,-1.,0.));
#739=VECTOR('',#738,1.);
#740=CARTESIAN_POINT('',(-1.5875,0.,30.4));
#741=LINE('',#740,#739);
#742=CARTESIAN_POINT('',(-1.5875,8.5875,30.4));
#743=VERTEX_POINT('',#742);
#744=EDGE_CURVE('E165',#743,#735,#741,.T.);
#745=ORIENTED_EDGE('',*,*,#744,.F.);
#746=DIRECTION('',(1.,0.,0.));
#747=VECTOR('',#746,1.);
#748=CARTESIAN_POINT('',(0.,8.5875,30.4));
#749=LINE('',#748,#747);
#750=EDGE_CURVE('E246',#743,#726,#749,.T.);
#751=ORIENTED_EDGE('',*,*,#750,.T.);
#752=EDGE_LOOP('',(#728,#737,#745,#751));
#753=FACE_BOUND('',#752,.T.);
#754=CARTESIAN_POINT('',(0.,0.,30.4));
#755=DIRECTION('',(0.,0.,1.));
#756=DIRECTION('',(1.,0.,0.));
#757=AXIS2_PLACEMENT_3D('',#754,#755,#756);
#758=CIRCLE('',#757,15.);
#759=CARTESIAN_POINT('',(15.,0.,30.4));
#760=VERTEX_POINT('',#759);
#761=EDGE_CURVE('E290',#760,#760,#758,.T.);
#762=ORIENTED_EDGE('',*,*,#761,.T.);
#763=EDGE_LOOP('',(#762));
#764=FACE_BOUND('',#763,.T.);
#765=ADVANCED_FACE('F296',(#753,#764),#718,.T.);
#766=CARTESIAN_POINT('',(0.,0.,30.4));
#767=DIRECTION('',(0.,0.,-1.));
#768=DIRECTION('',(-1.,0.,0.));
#769=AXIS2_PLACEMENT_3D('',#766,#767,#768);
#770=CYLINDRICAL_SURFACE('',#769,15.);
#771=CARTESIAN_POINT('',(15.,0.,22.4));
#772=CARTESIAN_POINT('',(14.9999988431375,-0.0923818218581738,22.4000039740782));
#773=CARTESIAN_POINT('',(14.9991375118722,-0.184823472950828,22.407784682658));
#774=CARTESIAN_POINT('',(14.9957843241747,-0.36714038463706,22.4387039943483));
#775=CARTESIAN_POINT('',(14.9932907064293,-0.457012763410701,22.4618591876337));
#776=CARTESIAN_POINT('',(14.9869542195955,-0.631524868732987,22.5228421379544));
#777=CARTESIAN_POINT('',(14.9831122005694,-0.716167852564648,22.560660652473));
#778=CARTESIAN_POINT('',(14.9745076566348,-0.877887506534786,22.649877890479));
#779=CARTESIAN_POINT('',(14.9697453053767,-0.95496559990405,22.7012740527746));
#780=CARTESIAN_POINT('',(14.9598099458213,-1.09971749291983,22.8164251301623));
#781=CARTESIAN_POINT('',(14.9546354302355,-1.16735402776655,22.880226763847));
#782=CARTESIAN_POINT('',(14.9444712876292,-1.29098229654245,23.0182777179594));
#783=CARTESIAN_POINT('',(14.9394816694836,-1.34697347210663,23.0925275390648));
#784=CARTESIAN_POINT('',(14.9302371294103,-1.44585644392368,23.2496041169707));
#785=CARTESIAN_POINT('',(14.9259841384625,-1.48871403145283,23.332452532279));
#786=CARTESIAN_POINT('',(14.9187136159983,-1.55989482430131,23.5042248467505));
#787=CARTESIAN_POINT('',(14.9156960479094,-1.58821845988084,23.5931485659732));
#788=CARTESIAN_POINT('',(14.9112520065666,-1.62941572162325,23.7741643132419));
#789=CARTESIAN_POINT('',(14.9098191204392,-1.64235163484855,23.8662420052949));
#790=CARTESIAN_POINT('',(14.908686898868,-1.65259886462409,24.0512718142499));
#791=CARTESIAN_POINT('',(14.908987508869,-1.64991067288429,24.1442239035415));
#792=CARTESIAN_POINT('',(14.9112824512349,-1.62903725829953,24.3279328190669));
#793=CARTESIAN_POINT('',(14.9132693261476,-1.61092026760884,24.4186975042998));
#794=CARTESIAN_POINT('',(14.9187012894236,-1.55980980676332,24.5958902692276));
#795=CARTESIAN_POINT('',(14.9221464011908,-1.52681609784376,24.682318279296));
#796=CARTESIAN_POINT('',(14.9301152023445,-1.44681419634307,24.8485985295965));
#797=CARTESIAN_POINT('',(14.9346411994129,-1.39977596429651,24.9284362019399));
#798=CARTESIAN_POINT('',(14.944259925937,-1.29304180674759,25.0791099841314));
#799=CARTESIAN_POINT('',(14.9493526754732,-1.23334543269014,25.1499457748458));
#800=CARTESIAN_POINT('',(14.9595642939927,-1.10260955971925,25.2810013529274));
#801=CARTESIAN_POINT('',(14.9646831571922,-1.03151117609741,25.341162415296));
#802=CARTESIAN_POINT('',(14.9743446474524,-0.880193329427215,25.4487048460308));
#803=CARTESIAN_POINT('',(14.978887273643,-0.799973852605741,25.496086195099));
#804=CARTESIAN_POINT('',(14.9868864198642,-0.632648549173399,25.5767227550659));
#805=CARTESIAN_POINT('',(14.9903426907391,-0.545541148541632,25.609974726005));
#806=CARTESIAN_POINT('',(14.9957772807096,-0.366932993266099,25.6613642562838));
#807=CARTESIAN_POINT('',(14.9977556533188,-0.275432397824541,25.6795023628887));
#808=CARTESIAN_POINT('',(15.0000046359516,-0.0911434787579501,25.7000741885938));
#809=CARTESIAN_POINT('',(15.0002840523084,0.00163570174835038,25.7025888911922));
#810=CARTESIAN_POINT('',(14.9991273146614,0.186294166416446,25.6920556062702));
#811=CARTESIAN_POINT('',(14.9976911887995,0.278173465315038,25.6790078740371));
#812=CARTESIAN_POINT('',(14.9932703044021,0.458188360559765,25.6377873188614));
#813=CARTESIAN_POINT('',(14.9902894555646,0.546332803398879,25.6096526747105));
#814=CARTESIAN_POINT('',(14.9831132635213,0.716651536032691,25.5390963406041));
#815=CARTESIAN_POINT('',(14.9789178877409,0.798825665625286,25.4966742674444));
#816=CARTESIAN_POINT('',(14.9697593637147,0.955235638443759,25.3985482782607));
#817=CARTESIAN_POINT('',(14.9647931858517,1.02943811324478,25.3427914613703));
#818=CARTESIAN_POINT('',(14.9546593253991,1.16746002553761,25.219654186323));
#819=CARTESIAN_POINT('',(14.9494916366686,1.23127914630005,25.1522733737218));
#820=CARTESIAN_POINT('',(14.9395104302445,1.34700625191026,25.0074461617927));
#821=CARTESIAN_POINT('',(14.9346985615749,1.39886088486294,24.9299570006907));
#822=CARTESIAN_POINT('',(14.9259997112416,1.48881961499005,24.7673223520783));
#823=CARTESIAN_POINT('',(14.9221127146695,1.52692393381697,24.682176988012));
#824=CARTESIAN_POINT('',(14.9157144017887,1.58821216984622,24.5068258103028));
#825=CARTESIAN_POINT('',(14.913200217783,1.61142720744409,24.4166309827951));
#826=CARTESIAN_POINT('',(14.9098235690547,1.64237859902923,24.2335942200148));
#827=CARTESIAN_POINT('',(14.9089610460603,1.65011549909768,24.1407523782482));
#828=CARTESIAN_POINT('',(14.9089867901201,1.6498825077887,23.9555874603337));
#829=CARTESIAN_POINT('',(14.9098657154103,1.64199642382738,23.8632642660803));
#830=CARTESIAN_POINT('',(14.9132553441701,1.61091769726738,23.6812632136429));
#831=CARTESIAN_POINT('',(14.9157660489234,1.58772504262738,23.59158535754));
#832=CARTESIAN_POINT('',(14.9221336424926,1.52671583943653,23.4174251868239));
#833=CARTESIAN_POINT('',(14.9259902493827,1.48890235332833,23.3329417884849));
#834=CARTESIAN_POINT('',(14.9346156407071,1.39973329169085,23.1715068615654));
#835=CARTESIAN_POINT('',(14.9393844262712,1.34837769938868,23.094555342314));
#836=CARTESIAN_POINT('',(14.9493275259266,1.23326864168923,22.9499392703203));
#837=CARTESIAN_POINT('',(14.9545038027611,1.16945266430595,22.8823246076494));
#838=CARTESIAN_POINT('',(14.9646609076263,1.03136150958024,22.7587290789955));
#839=CARTESIAN_POINT('',(14.969641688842,0.95708384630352,22.7027509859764));
#840=CARTESIAN_POINT('',(14.9788625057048,0.799929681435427,22.6038812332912));
#841=CARTESIAN_POINT('',(14.9831002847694,0.717028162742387,22.5610291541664));
#842=CARTESIAN_POINT('',(14.9903338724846,0.545209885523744,22.4899127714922));
#843=CARTESIAN_POINT('',(14.993331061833,0.456299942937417,22.4616322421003));
#844=CARTESIAN_POINT('',(14.9970040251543,0.305751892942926,22.4274087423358));
#845=CARTESIAN_POINT('',(14.9981221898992,0.245071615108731,22.4171447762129));
#846=CARTESIAN_POINT('',(14.9996205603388,0.122936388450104,22.4034391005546));
#847=CARTESIAN_POINT('',(15.0000007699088,0.0614814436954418,22.3999973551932));
#848=CARTESIAN_POINT('',(15.,0.,22.4));
#849=B_SPLINE_CURVE_WITH_KNOTS('',3,(#771,#772,#773,#774,#775,#776,#777,#778,#779,#780,#781,
#782,#783,#784,#785,#786,#787,#788,#789,#790,#791,#792,#793,#794,#795,#796,#797,#798,#799,#800,
#801,#802,#803,#804,#805,#806,#807,#808,#809,#810,#811,#812,#813,#814,#815,#816,#817,#818,#819,
#820,#821,#822,#823,#824,#825,#826,#827,#828,#829,#830,#831,#832,#833,#834,#835,#836,#837,#838,
#839,#840,#841,#842,#843,#844,#845,#846,#847,#848),.UNSPECIFIED.,.T.,.F.,(4,2,2,2,2,2,2,2,2,2,2,
2,2,2,2,2,2,2,2,2,2,2,2,2,2,2,2,2,2,2,2,2,2,2,2,2,2,2,4),(0.,0.276920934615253,
0.554141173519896,0.831186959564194,1.10818052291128,1.38623817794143,1.66430916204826,
1.94309839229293,2.22187936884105,2.49952800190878,2.77716789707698,3.05358629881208,
3.33000913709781,3.6070274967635,3.88405567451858,4.16256356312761,4.44107187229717,
4.71964401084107,4.99820606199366,5.27532298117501,5.55243535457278,5.82884975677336,
6.1052715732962,6.38280873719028,6.6603543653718,6.93911468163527,7.21787050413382,
7.49604177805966,7.77420323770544,8.05087657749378,8.32755013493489,8.60416577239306,
8.88078175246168,9.15882288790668,9.4369302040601,9.71586805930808,9.99449463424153,
10.1787905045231,10.3630854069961),.UNSPECIFIED.);
#850=CARTESIAN_POINT('',(15.,0.,22.4));
#851=VERTEX_POINT('',#850);
#852=EDGE_CURVE('E262',#851,#851,#849,.T.);
#853=ORIENTED_EDGE('',*,*,#852,.T.);
#854=EDGE_LOOP('',(#853));
#855=FACE_BOUND('',#854,.T.);
#856=CARTESIAN_POINT('',(0.,15.,25.7));
#857=CARTESIAN_POINT('',(-0.0923818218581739,14.9999988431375,25.6999960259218));
#858=CARTESIAN_POINT('',(-0.184823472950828,14.9991375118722,25.692215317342));
#859=CARTESIAN_POINT('',(-0.367140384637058,14.9957843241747,25.6612960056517));
#860=CARTESIAN_POINT('',(-0.457012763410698,14.9932907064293,25.6381408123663));
#861=CARTESIAN_POINT('',(-0.631524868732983,14.9869542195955,25.5771578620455));
#862=CARTESIAN_POINT('',(-0.716167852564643,14.9831122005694,25.539339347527));
#863=CARTESIAN_POINT('',(-0.877887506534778,14.9745076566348,25.4501221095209));
#864=CARTESIAN_POINT('',(-0.95496559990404,14.9697453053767,25.3987259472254));
#865=CARTESIAN_POINT('',(-1.09971749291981,14.9598099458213,25.2835748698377));
#866=CARTESIAN_POINT('',(-1.16735402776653,14.9546354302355,25.219773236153));
#867=CARTESIAN_POINT('',(-1.29098229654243,14.9444712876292,25.0817222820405));
#868=CARTESIAN_POINT('',(-1.34697347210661,14.9394816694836,25.0074724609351));
#869=CARTESIAN_POINT('',(-1.44585644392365,14.9302371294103,24.8503958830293));
#870=CARTESIAN_POINT('',(-1.48871403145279,14.9259841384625,24.767547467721));
#871=CARTESIAN_POINT('',(-1.55989482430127,14.9187136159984,24.5957751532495));
#872=CARTESIAN_POINT('',(-1.5882184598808,14.9156960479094,24.5068514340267));
#873=CARTESIAN_POINT('',(-1.6294157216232,14.9112520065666,24.325835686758));
#874=CARTESIAN_POINT('',(-1.6423516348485,14.9098191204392,24.233757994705));
#875=CARTESIAN_POINT('',(-1.65259886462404,14.908686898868,24.0487281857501));
#876=CARTESIAN_POINT('',(-1.64991067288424,14.908987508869,23.9557760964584));
#877=CARTESIAN_POINT('',(-1.62903725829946,14.9112824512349,23.7720671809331));
#878=CARTESIAN_POINT('',(-1.61092026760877,14.9132693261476,23.6813024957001));
#879=CARTESIAN_POINT('',(-1.55980980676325,14.9187012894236,23.5041097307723));
#880=CARTESIAN_POINT('',(-1.52681609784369,14.9221464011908,23.4176817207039));
#881=CARTESIAN_POINT('',(-1.44681419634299,14.9301152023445,23.2514014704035));
#882=CARTESIAN_POINT('',(-1.39977596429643,14.9346411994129,23.1715637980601));
#883=CARTESIAN_POINT('',(-1.29304180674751,14.944259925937,23.0208900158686));
#884=CARTESIAN_POINT('',(-1.23334543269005,14.9493526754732,22.9500542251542));
#885=CARTESIAN_POINT('',(-1.10260955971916,14.9595642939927,22.8189986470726));
#886=CARTESIAN_POINT('',(-1.03151117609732,14.9646831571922,22.758837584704));
#887=CARTESIAN_POINT('',(-0.880193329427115,14.9743446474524,22.6512951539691));
#888=CARTESIAN_POINT('',(-0.799973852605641,14.978887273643,22.603913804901));
#889=CARTESIAN_POINT('',(-0.632648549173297,14.9868864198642,22.5232772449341));
#890=CARTESIAN_POINT('',(-0.545541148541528,14.9903426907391,22.490025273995));
#891=CARTESIAN_POINT('',(-0.366932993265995,14.9957772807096,22.4386357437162));
#892=CARTESIAN_POINT('',(-0.275432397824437,14.9977556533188,22.4204976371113));
#893=CARTESIAN_POINT('',(-0.091143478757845,15.0000046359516,22.3999258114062));
#894=CARTESIAN_POINT('',(0.00163570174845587,15.0002840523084,22.3974111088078));
#895=CARTESIAN_POINT('',(0.186294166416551,14.9991273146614,22.4079443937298));
#896=CARTESIAN_POINT('',(0.278173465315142,14.9976911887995,22.4209921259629));
#897=CARTESIAN_POINT('',(0.458188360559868,14.9932703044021,22.4622126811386));
#898=CARTESIAN_POINT('',(0.546332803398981,14.9902894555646,22.4903473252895));
#899=CARTESIAN_POINT('',(0.716651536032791,14.9831132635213,22.5609036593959));
#900=CARTESIAN_POINT('',(0.798825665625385,14.9789178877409,22.6033257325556));
#901=CARTESIAN_POINT('',(0.955235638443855,14.9697593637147,22.7014517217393));
#902=CARTESIAN_POINT('',(1.02943811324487,14.9647931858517,22.7572085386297));
#903=CARTESIAN_POINT('',(1.1674600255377,14.9546593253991,22.8803458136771));
#904=CARTESIAN_POINT('',(1.23127914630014,14.9494916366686,22.9477266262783));
#905=CARTESIAN_POINT('',(1.34700625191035,14.9395104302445,23.0925538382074));
#906=CARTESIAN_POINT('',(1.39886088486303,14.9346985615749,23.1700429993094));
#907=CARTESIAN_POINT('',(1.48881961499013,14.9259997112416,23.3326776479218));
#908=CARTESIAN_POINT('',(1.52692393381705,14.9221127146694,23.417823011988));
#909=CARTESIAN_POINT('',(1.58821216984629,14.9157144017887,23.5931741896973));
#910=CARTESIAN_POINT('',(1.61142720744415,14.913200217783,23.6833690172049));
#911=CARTESIAN_POINT('',(1.64237859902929,14.9098235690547,23.8664057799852));
#912=CARTESIAN_POINT('',(1.65011549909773,14.9089610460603,23.9592476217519));
#913=CARTESIAN_POINT('',(1.64988250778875,14.9089867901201,24.1444125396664));
#914=CARTESIAN_POINT('',(1.64199642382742,14.9098657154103,24.2367357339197));
#915=CARTESIAN_POINT('',(1.61091769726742,14.9132553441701,24.4187367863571));
#916=CARTESIAN_POINT('',(1.58772504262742,14.9157660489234,24.5084146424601));
#917=CARTESIAN_POINT('',(1.52671583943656,14.9221336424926,24.6825748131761));
#918=CARTESIAN_POINT('',(1.48890235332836,14.9259902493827,24.7670582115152));
#919=CARTESIAN_POINT('',(1.39973329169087,14.9346156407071,24.9284931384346));
#920=CARTESIAN_POINT('',(1.3483776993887,14.9393844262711,25.005444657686));
#921=CARTESIAN_POINT('',(1.23326864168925,14.9493275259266,25.1500607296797));
#922=CARTESIAN_POINT('',(1.16945266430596,14.9545038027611,25.2176753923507));
#923=CARTESIAN_POINT('',(1.03136150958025,14.9646609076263,25.3412709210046));
#924=CARTESIAN_POINT('',(0.957083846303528,14.969641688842,25.3972490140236));
#925=CARTESIAN_POINT('',(0.799929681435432,14.9788625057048,25.4961187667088));
#926=CARTESIAN_POINT('',(0.717028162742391,14.9831002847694,25.5389708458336));
#927=CARTESIAN_POINT('',(0.545209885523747,14.9903338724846,25.6100872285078));
#928=CARTESIAN_POINT('',(0.456299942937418,14.993331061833,25.6383677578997));
#929=CARTESIAN_POINT('',(0.305751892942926,14.9970040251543,25.6725912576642));
#930=CARTESIAN_POINT('',(0.245071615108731,14.9981221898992,25.6828552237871));
#931=CARTESIAN_POINT('',(0.122936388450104,14.9996205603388,25.6965608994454));
#932=CARTESIAN_POINT('',(0.0614814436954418,15.0000007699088,25.7000026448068));
#933=CARTESIAN_POINT('',(0.,15.,25.7));
#934=B_SPLINE_CURVE_WITH_KNOTS('',3,(#856,#857,#858,#859,#860,#861,#862,#863,#864,#865,#866,
#867,#868,#869,#870,#871,#872,#873,#874,#875,#876,#877,#878,#879,#880,#881,#882,#883,#884,#885,
#886,#887,#888,#889,#890,#891,#892,#893,#894,#895,#896,#897,#898,#899,#900,#901,#902,#903,#904,
#905,#906,#907,#908,#909,#910,#911,#912,#913,#914,#915,#916,#917,#918,#919,#920,#921,#922,#923,
#924,#925,#926,#927,#928,#929,#930,#931,#932,#933),.UNSPECIFIED.,.T.,.F.,(4,2,2,2,2,2,2,2,2,2,2,
2,2,2,2,2,2,2,2,2,2,2,2,2,2,2,2,2,2,2,2,2,2,2,2,2,2,2,4),(0.,0.276920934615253,
0.554141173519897,0.831186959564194,1.10818052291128,1.38623817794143,1.66430916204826,
1.94309839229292,2.22187936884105,2.49952800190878,2.77716789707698,3.05358629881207,
3.33000913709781,3.6070274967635,3.88405567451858,4.16256356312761,4.44107187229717,
4.71964401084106,4.99820606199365,5.27532298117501,5.55243535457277,5.82884975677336,
6.1052715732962,6.38280873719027,6.66035436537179,6.93911468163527,7.21787050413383,
7.49604177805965,7.77420323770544,8.05087657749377,8.32755013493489,8.60416577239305,
8.88078175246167,9.15882288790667,9.43693020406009,9.71586805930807,9.99449463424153,
10.178790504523,10.3630854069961),.UNSPECIFIED.);
#935=CARTESIAN_POINT('',(0.,15.,25.7));
#936=VERTEX_POINT('',#935);
#937=EDGE_CURVE('E284',#936,#936,#934,.T.);
#938=ORIENTED_EDGE('',*,*,#937,.T.);
#939=EDGE_LOOP('',(#938));
#940=FACE_BOUND('',#939,.T.);
#941=ORIENTED_EDGE('',*,*,#761,.F.);
#942=EDGE_LOOP('',(#941));
#943=FACE_BOUND('',#942,.T.);
#944=ORIENTED_EDGE('',*,*,#130,.T.);
#945=EDGE_LOOP('',(#944));
#946=FACE_BOUND('',#945,.T.);
#947=ADVANCED_FACE('F292',(#855,#940,#943,#946),#770,.T.);
#948=CARTESIAN_POINT('',(0.,0.,30.4));
#949=DIRECTION('',(0.,0.,-1.));
#950=DIRECTION('',(-1.,0.,0.));
#951=AXIS2_PLACEMENT_3D('',#948,#949,#950);
#952=CYLINDRICAL_SURFACE('',#951,7.);
#953=CARTESIAN_POINT('',(-1.80954948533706,6.76206556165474,24.651236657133));
#954=CARTESIAN_POINT('',(-1.92479504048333,6.73054483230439,24.2651017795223));
#955=CARTESIAN_POINT('',(-1.92550157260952,6.73035039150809,23.8372119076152));
#956=CARTESIAN_POINT('',(-1.8094695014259,6.76208696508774,23.4484929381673));
#957=B_SPLINE_CURVE_WITH_KNOTS('',3,(#953,#954,#955,#956),.UNSPECIFIED.,.F.,.F.,(4,4),
(0.00598488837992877,0.00720026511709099),.UNSPECIFIED.);
#958=CARTESIAN_POINT('',(-1.83459558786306,6.75526401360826,23.540499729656));
#959=VERTEX_POINT('',#958);
#960=CARTESIAN_POINT('',(-1.83453024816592,6.75533113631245,24.5594795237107));
#961=VERTEX_POINT('',#960);
#962=EDGE_CURVE('E613',#959,#961,#957,.F.);
#963=ORIENTED_EDGE('',*,*,#962,.T.);
#964=DIRECTION('',(0.,0.,-1.));
#965=VECTOR('',#964,1.);
#966=CARTESIAN_POINT('',(-1.83444761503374,6.75535357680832,30.4));
#967=LINE('',#966,#965);
#968=CARTESIAN_POINT('',(-1.83444761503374,6.75535357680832,29.4));
#969=VERTEX_POINT('',#968);
#970=EDGE_CURVE('E234',#961,#969,#967,.F.);
#971=ORIENTED_EDGE('',*,*,#970,.T.);
#972=CARTESIAN_POINT('',(0.,0.,29.4));
#973=DIRECTION('',(0.,0.,1.));
#974=DIRECTION('',(1.,0.,0.));
#975=AXIS2_PLACEMENT_3D('',#972,#973,#974);
#976=CIRCLE('',#975,7.);
#977=CARTESIAN_POINT('',(1.83444761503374,6.75535357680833,29.4));
#978=VERTEX_POINT('',#977);
#979=EDGE_CURVE('E545',#969,#978,#976,.T.);
#980=ORIENTED_EDGE('',*,*,#979,.T.);
#981=DIRECTION('',(0.,0.,-1.));
#982=VECTOR('',#981,1.);
#983=CARTESIAN_POINT('',(1.83444761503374,6.75535357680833,30.4));
#984=LINE('',#983,#982);
#985=CARTESIAN_POINT('',(1.83462413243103,6.7552563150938,24.5595079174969));
#986=VERTEX_POINT('',#985);
#987=EDGE_CURVE('E571',#978,#986,#984,.T.);
#988=ORIENTED_EDGE('',*,*,#987,.T.);
#989=CARTESIAN_POINT('',(1.80961520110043,6.76204797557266,23.4489856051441));
#990=CARTESIAN_POINT('',(1.92455575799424,6.73061065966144,23.834215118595));
#991=CARTESIAN_POINT('',(1.92566078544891,6.73030583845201,24.262703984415));
#992=CARTESIAN_POINT('',(1.80954635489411,6.76206639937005,24.6512472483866));
#993=B_SPLINE_CURVE_WITH_KNOTS('',3,(#989,#990,#991,#992),.UNSPECIFIED.,.F.,.F.,(4,4),
(0.00592011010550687,0.00713496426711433),.UNSPECIFIED.);
#994=CARTESIAN_POINT('',(1.83452901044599,6.75533147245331,23.5405208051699));
#995=VERTEX_POINT('',#994);
#996=EDGE_CURVE('E574',#986,#995,#993,.F.);
#997=ORIENTED_EDGE('',*,*,#996,.T.);
#998=DIRECTION('',(0.,0.,-1.));
#999=VECTOR('',#998,1.);
#1000=CARTESIAN_POINT('',(1.83444761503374,6.75535357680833,30.4));
#1001=LINE('',#1000,#999);
#1002=CARTESIAN_POINT('',(1.83444761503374,6.75535357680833,21.5));
#1003=VERTEX_POINT('',#1002);
#1004=EDGE_CURVE('E590',#995,#1003,#1001,.T.);
#1005=ORIENTED_EDGE('',*,*,#1004,.T.);
#1006=CARTESIAN_POINT('',(-1.83444761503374,6.75535357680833,21.5));
#1007=CARTESIAN_POINT('',(-1.83587406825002,6.75382792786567,20.9834486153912));
#1008=CARTESIAN_POINT('',(-1.63515455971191,6.81392584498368,20.4845539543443));
#1009=CARTESIAN_POINT('',(-0.958112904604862,6.94379794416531,19.7676432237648));
#1010=CARTESIAN_POINT('',(-0.481714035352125,7.00004140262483,19.5576974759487));
#1011=CARTESIAN_POINT('',(0.48505811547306,6.99995819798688,19.5578705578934));
#1012=CARTESIAN_POINT('',(0.959489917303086,6.94366722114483,19.7687266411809));
#1013=CARTESIAN_POINT('',(1.63487615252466,6.81384944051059,20.4846332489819));
#1014=CARTESIAN_POINT('',(1.83620868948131,6.75370998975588,20.9879356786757));
#1015=CARTESIAN_POINT('',(1.83444761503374,6.75535357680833,21.5));
#1016=B_SPLINE_CURVE_WITH_KNOTS('',3,(#1006,#1007,#1008,#1009,#1010,#1011,#1012,#1013,#1014,
#1015),.UNSPECIFIED.,.F.,.F.,(4,2,2,2,4),(0.,0.00152425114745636,0.00304850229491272,
0.00457275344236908,0.00609700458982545),.UNSPECIFIED.);
#1017=CARTESIAN_POINT('',(-1.83444761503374,6.75535357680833,21.5));
#1018=VERTEX_POINT('',#1017);
#1019=EDGE_CURVE('E597',#1003,#1018,#1016,.F.);
#1020=ORIENTED_EDGE('',*,*,#1019,.T.);
#1021=DIRECTION('',(0.,0.,-1.));
#1022=VECTOR('',#1021,1.);
#1023=CARTESIAN_POINT('',(-1.83444761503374,6.75535357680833,30.4));
#1024=LINE('',#1023,#1022);
#1025=EDGE_CURVE('E606',#1018,#959,#1024,.F.);
#1026=ORIENTED_EDGE('',*,*,#1025,.T.);
#1027=EDGE_LOOP('',(#963,#971,#980,#988,#997,#1005,#1020,#1026));
#1028=FACE_BOUND('',#1027,.T.);
#1029=CARTESIAN_POINT('',(7.,0.,22.4));
#1030=CARTESIAN_POINT('',(6.99999836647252,-0.0913287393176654,22.4000028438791));
#1031=CARTESIAN_POINT('',(6.99819467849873,-0.182690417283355,22.4076082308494));
#1032=CARTESIAN_POINT('',(6.9911739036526,-0.362806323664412,22.4377899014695));
#1033=CARTESIAN_POINT('',(6.98595464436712,-0.451558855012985,22.4603757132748));
#1034=CARTESIAN_POINT('',(6.97268218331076,-0.623828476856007,22.5197617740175));
#1035=CARTESIAN_POINT('',(6.96463217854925,-0.707351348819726,22.556545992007));
#1036=CARTESIAN_POINT('',(6.9465609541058,-0.867039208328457,22.6432308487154));
#1037=CARTESIAN_POINT('',(6.93653972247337,-0.943204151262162,22.693131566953));
#1038=CARTESIAN_POINT('',(6.91541181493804,-1.08742143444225,22.8056068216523));
#1039=CARTESIAN_POINT('',(6.90428991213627,-1.15531854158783,22.8683775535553));
#1040=CARTESIAN_POINT('',(6.88231817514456,-1.27972508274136,23.0043904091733));
#1041=CARTESIAN_POINT('',(6.87146836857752,-1.33623336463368,23.0776335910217));
#1042=CARTESIAN_POINT('',(6.85111743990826,-1.43696684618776,23.233690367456));
#1043=CARTESIAN_POINT('',(6.84163573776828,-1.4810223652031,23.3166162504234));
#1044=CARTESIAN_POINT('',(6.82531505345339,-1.55450989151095,23.4889557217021));
#1045=CARTESIAN_POINT('',(6.81847569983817,-1.58394395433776,23.5783683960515));
#1046=CARTESIAN_POINT('',(6.80836995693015,-1.6268312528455,23.759446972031));
#1047=CARTESIAN_POINT('',(6.80504168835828,-1.64056162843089,23.8510437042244));
#1048=CARTESIAN_POINT('',(6.80214944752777,-1.65251435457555,24.0352963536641));
#1049=CARTESIAN_POINT('',(6.80258493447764,-1.65073893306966,24.127952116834));
#1050=CARTESIAN_POINT('',(6.80711518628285,-1.63195247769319,24.3095991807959));
#1051=CARTESIAN_POINT('',(6.81113158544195,-1.6152677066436,24.3986264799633));
#1052=CARTESIAN_POINT('',(6.82224669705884,-1.56765494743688,24.5725815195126));
#1053=CARTESIAN_POINT('',(6.82934560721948,-1.53672604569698,24.657508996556));
#1054=CARTESIAN_POINT('',(6.84590028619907,-1.46121486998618,24.8217483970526));
#1055=CARTESIAN_POINT('',(6.85537691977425,-1.4165108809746,24.9010021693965));
#1056=CARTESIAN_POINT('',(6.87560701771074,-1.31480384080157,25.0510021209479));
#1057=CARTESIAN_POINT('',(6.88636068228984,-1.25779885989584,25.1217469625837));
#1058=CARTESIAN_POINT('',(6.90826612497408,-1.13140044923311,25.2545947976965));
#1059=CARTESIAN_POINT('',(6.91942110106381,-1.06173067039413,25.316434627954));
#1060=CARTESIAN_POINT('',(6.94062641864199,-0.912878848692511,25.4275996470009));
#1061=CARTESIAN_POINT('',(6.9506767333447,-0.833696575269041,25.4769245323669));
#1062=CARTESIAN_POINT('',(6.96858169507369,-0.667717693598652,25.5617410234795));
#1063=CARTESIAN_POINT('',(6.97643016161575,-0.580900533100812,25.5971937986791));
#1064=CARTESIAN_POINT('',(6.98900179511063,-0.402313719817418,25.6529315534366));
#1065=CARTESIAN_POINT('',(6.99372549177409,-0.310544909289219,25.6732191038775));
#1066=CARTESIAN_POINT('',(6.9994383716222,-0.126913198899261,25.6976576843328));
#1067=CARTESIAN_POINT('',(7.00051059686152,-0.035100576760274,25.7021675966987));
#1068=CARTESIAN_POINT('',(6.99903444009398,0.147966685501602,25.6959017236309));
#1069=CARTESIAN_POINT('',(6.99648634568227,0.23922136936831,25.6851271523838));
#1070=CARTESIAN_POINT('',(6.98810869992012,0.417362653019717,25.6488949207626));
#1071=CARTESIAN_POINT('',(6.98232213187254,0.504290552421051,25.6236294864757));
#1072=CARTESIAN_POINT('',(6.96811723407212,0.672672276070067,25.5593493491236));
#1073=CARTESIAN_POINT('',(6.95969865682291,0.754125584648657,25.5203333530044));
#1074=CARTESIAN_POINT('',(6.94096161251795,0.910700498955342,25.4289395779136));
#1075=CARTESIAN_POINT('',(6.93061465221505,0.985698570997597,25.376356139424));
#1076=CARTESIAN_POINT('',(6.90921937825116,1.12593444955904,25.2595866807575));
#1077=CARTESIAN_POINT('',(6.89817095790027,1.19117076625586,25.1953988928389));
#1078=CARTESIAN_POINT('',(6.8763246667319,1.31148229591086,25.055584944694));
#1079=CARTESIAN_POINT('',(6.86553738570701,1.36630717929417,24.9797413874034));
#1080=CARTESIAN_POINT('',(6.84570445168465,1.46244648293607,24.8197152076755));
#1081=CARTESIAN_POINT('',(6.83665872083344,1.50376150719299,24.7355329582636));
#1082=CARTESIAN_POINT('',(6.82142736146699,1.57141076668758,24.5616787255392));
#1083=CARTESIAN_POINT('',(6.81522499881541,1.59783286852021,24.4720424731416));
#1084=CARTESIAN_POINT('',(6.80635903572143,1.63519178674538,24.2894343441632));
#1085=CARTESIAN_POINT('',(6.80369476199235,1.64613154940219,24.1964631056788));
#1086=CARTESIAN_POINT('',(6.80225382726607,1.6520744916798,24.0123599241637));
#1087=CARTESIAN_POINT('',(6.80337995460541,1.64747616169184,23.9212413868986));
#1088=CARTESIAN_POINT('',(6.80917049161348,1.62337546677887,23.7411176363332));
#1089=CARTESIAN_POINT('',(6.81383484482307,1.60387333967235,23.6521123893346));
#1090=CARTESIAN_POINT('',(6.82612522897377,1.55072477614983,23.4791198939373));
#1091=CARTESIAN_POINT('',(6.83373724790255,1.51714519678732,23.3951110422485));
#1092=CARTESIAN_POINT('',(6.85106877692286,1.43684939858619,23.2338634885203));
#1093=CARTESIAN_POINT('',(6.8607885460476,1.39013156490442,23.1566256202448));
#1094=CARTESIAN_POINT('',(6.88152384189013,1.28360204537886,23.0091683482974));
#1095=CARTESIAN_POINT('',(6.89256431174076,1.22351026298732,22.9391547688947));
#1096=CARTESIAN_POINT('',(6.91453965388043,1.09249493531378,22.8100751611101));
#1097=CARTESIAN_POINT('',(6.92547450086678,1.02156885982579,22.7510116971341));
#1098=CARTESIAN_POINT('',(6.9462096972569,0.86956273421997,22.64461714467));
#1099=CARTESIAN_POINT('',(6.95598967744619,0.788341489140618,22.5974835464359));
#1100=CARTESIAN_POINT('',(6.97310375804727,0.618909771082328,22.517613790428));
#1101=CARTESIAN_POINT('',(6.98043975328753,0.530704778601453,22.4848664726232));
#1102=CARTESIAN_POINT('',(6.99064750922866,0.368778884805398,22.4400257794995));
#1103=CARTESIAN_POINT('',(6.99413174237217,0.295881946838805,22.4250467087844));
#1104=CARTESIAN_POINT('',(6.99880858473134,0.148663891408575,22.4050329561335));
#1105=CARTESIAN_POINT('',(7.00000132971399,0.0743428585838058,22.3999976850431));
#1106=CARTESIAN_POINT('',(7.,0.,22.4));
#1107=B_SPLINE_CURVE_WITH_KNOTS('',3,(#1029,#1030,#1031,#1032,#1033,#1034,#1035,#1036,#1037,
#1038,#1039,#1040,#1041,#1042,#1043,#1044,#1045,#1046,#1047,#1048,#1049,#1050,#1051,#1052,#1053,
#1054,#1055,#1056,#1057,#1058,#1059,#1060,#1061,#1062,#1063,#1064,#1065,#1066,#1067,#1068,#1069,
#1070,#1071,#1072,#1073,#1074,#1075,#1076,#1077,#1078,#1079,#1080,#1081,#1082,#1083,#1084,#1085,
#1086,#1087,#1088,#1089,#1090,#1091,#1092,#1093,#1094,#1095,#1096,#1097,#1098,#1099,#1100,#1101,
#1102,#1103,#1104,#1105,#1106),.UNSPECIFIED.,.T.,.F.,(4,2,2,2,2,2,2,2,2,2,2,2,2,2,2,2,2,2,2,2,2,
2,2,2,2,2,2,2,2,2,2,2,2,2,2,2,2,2,4),(0.,0.273713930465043,0.547602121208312,0.821181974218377,
1.09476348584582,1.37287554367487,1.65101572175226,1.93278083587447,2.21450632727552,
2.49117922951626,2.76781237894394,3.03853628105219,3.30927754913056,3.58248319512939,
3.85573173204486,4.13587649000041,4.41602803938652,4.6969582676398,4.97784086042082,
5.25229133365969,5.52672000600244,5.79758981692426,6.06848510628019,6.34375631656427,
6.61906949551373,6.90033819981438,7.18159432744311,7.46117322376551,7.74069890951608,
8.0131108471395,8.28551843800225,8.55664670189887,8.82780830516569,9.10529722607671,
9.3828510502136,9.66473658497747,9.94640306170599,10.1692231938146,10.3920301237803),.UNSPECIFIED.);
#1108=CARTESIAN_POINT('',(7.,0.,22.4));
#1109=VERTEX_POINT('',#1108);
#1110=EDGE_CURVE('E257',#1109,#1109,#1107,.T.);
#1111=ORIENTED_EDGE('',*,*,#1110,.F.);
#1112=EDGE_LOOP('',(#1111));
#1113=FACE_BOUND('',#1112,.T.);
#1114=ORIENTED_EDGE('',*,*,#386,.T.);
#1115=EDGE_LOOP('',(#1114));
#1116=FACE_BOUND('',#1115,.T.);
#1117=ADVANCED_FACE('F273',(#1028,#1113,#1116),#952,.F.);
#1118=CARTESIAN_POINT('',(0.,15.,24.05));
#1119=DIRECTION('',(0.,1.,0.));
#1120=DIRECTION('',(0.,0.,1.));
#1121=AXIS2_PLACEMENT_3D('',#1118,#1119,#1120);
#1122=CYLINDRICAL_SURFACE('',#1121,1.64999999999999);
#1123=DIRECTION('',(0.,1.,0.));
#1124=VECTOR('',#1123,1.);
#1125=CARTESIAN_POINT('',(-1.5875,15.,24.4998263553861));
#1126=LINE('',#1125,#1124);
#1127=CARTESIAN_POINT('',(-1.5875,8.5875,24.4998263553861));
#1128=VERTEX_POINT('',#1127);
#1129=CARTESIAN_POINT('',(-1.58874850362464,7.16130364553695,24.5001097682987));
#1130=VERTEX_POINT('',#1129);
#1131=EDGE_CURVE('E579',#1128,#1130,#1126,.F.);
#1132=ORIENTED_EDGE('',*,*,#1131,.T.);
#1133=CARTESIAN_POINT('',(-1.57439277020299,7.16766450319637,23.5562516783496));
#1134=CARTESIAN_POINT('',(-1.67535056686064,7.13402442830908,23.8753324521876));
#1135=CARTESIAN_POINT('',(-1.67473582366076,7.13423053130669,24.2265667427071));
#1136=CARTESIAN_POINT('',(-1.5744623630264,7.16764181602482,24.5435263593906));
#1137=B_SPLINE_CURVE_WITH_KNOTS('',3,(#1133,#1134,#1135,#1136),.UNSPECIFIED.,.F.,.F.,(4,4),
(0.00598488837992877,0.00720026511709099),.UNSPECIFIED.);
#1138=CARTESIAN_POINT('',(-1.58646787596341,7.15969752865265,23.6001666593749));
#1139=VERTEX_POINT('',#1138);
#1140=EDGE_CURVE('E779',#1130,#1139,#1137,.F.);
#1141=ORIENTED_EDGE('',*,*,#1140,.T.);
#1142=DIRECTION('',(0.,1.,0.));
#1143=VECTOR('',#1142,1.);
#1144=CARTESIAN_POINT('',(-1.5875,15.,23.6001736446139));
#1145=LINE('',#1144,#1143);
#1146=CARTESIAN_POINT('',(-1.5875,8.5875,23.6001736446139));
#1147=VERTEX_POINT('',#1146);
#1148=EDGE_CURVE('E144',#1139,#1147,#1145,.T.);
#1149=ORIENTED_EDGE('',*,*,#1148,.T.);
#1150=CARTESIAN_POINT('',(0.,8.5875,24.05));
#1151=DIRECTION('',(0.,-1.,0.));
#1152=DIRECTION('',(0.,0.,-1.));
#1153=AXIS2_PLACEMENT_3D('',#1150,#1151,#1152);
#1154=CIRCLE('',#1153,1.64999999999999);
#1155=CARTESIAN_POINT('',(1.5875,8.5875,23.6001736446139));
#1156=VERTEX_POINT('',#1155);
#1157=EDGE_CURVE('E142',#1156,#1147,#1154,.F.);
#1158=ORIENTED_EDGE('',*,*,#1157,.F.);
#1159=DIRECTION('',(0.,1.,0.));
#1160=VECTOR('',#1159,1.);
#1161=CARTESIAN_POINT('',(1.5875,15.,23.6001736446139));
#1162=LINE('',#1161,#1160);
#1163=CARTESIAN_POINT('',(1.58874834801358,7.16130396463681,23.5998903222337));
#1164=VERTEX_POINT('',#1163);
#1165=EDGE_CURVE('E242',#1156,#1164,#1162,.F.);
#1166=ORIENTED_EDGE('',*,*,#1165,.T.);
#1167=CARTESIAN_POINT('',(1.57445963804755,7.16764270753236,24.5435350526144));
#1168=CARTESIAN_POINT('',(1.67548909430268,7.13397720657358,24.2245985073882));
#1169=CARTESIAN_POINT('',(1.67452762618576,7.13430031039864,23.8728725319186));
#1170=CARTESIAN_POINT('',(1.57451954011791,7.16762317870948,23.5566560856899));
#1171=B_SPLINE_CURVE_WITH_KNOTS('',3,(#1167,#1168,#1169,#1170),.UNSPECIFIED.,.F.,.F.,(4,4),
(0.00592011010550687,0.00713496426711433),.UNSPECIFIED.);
#1172=CARTESIAN_POINT('',(1.58646838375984,7.15969338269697,24.4998344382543));
#1173=VERTEX_POINT('',#1172);
#1174=EDGE_CURVE('E241',#1164,#1173,#1171,.F.);
#1175=ORIENTED_EDGE('',*,*,#1174,.T.);
#1176=DIRECTION('',(0.,1.,0.));
#1177=VECTOR('',#1176,1.);
#1178=CARTESIAN_POINT('',(1.5875,15.,24.4998263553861));
#1179=LINE('',#1178,#1177);
#1180=CARTESIAN_POINT('',(1.5875,8.5875,24.4998263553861));
#1181=VERTEX_POINT('',#1180);
#1182=EDGE_CURVE('E248',#1173,#1181,#1179,.T.);
#1183=ORIENTED_EDGE('',*,*,#1182,.T.);
#1184=EDGE_CURVE('E572',#1128,#1181,#1154,.F.);
#1185=ORIENTED_EDGE('',*,*,#1184,.F.);
#1186=EDGE_LOOP('',(#1132,#1141,#1149,#1158,#1166,#1175,#1183,#1185));
#1187=FACE_BOUND('',#1186,.T.);
#1188=ORIENTED_EDGE('',*,*,#937,.F.);
#1189=EDGE_LOOP('',(#1188));
#1190=FACE_BOUND('',#1189,.T.);
#1191=ADVANCED_FACE('F269',(#1187,#1190),#1122,.F.);
#1192=CARTESIAN_POINT('',(15.,0.,24.05));
#1193=DIRECTION('',(1.,0.,0.));
#1194=DIRECTION('',(0.,0.,-1.));
#1195=AXIS2_PLACEMENT_3D('',#1192,#1193,#1194);
#1196=CYLINDRICAL_SURFACE('',#1195,1.64999999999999);
#1197=ORIENTED_EDGE('',*,*,#1110,.T.);
#1198=EDGE_LOOP('',(#1197));
#1199=FACE_BOUND('',#1198,.T.);
#1200=ORIENTED_EDGE('',*,*,#852,.F.);
#1201=EDGE_LOOP('',(#1200));
#1202=FACE_BOUND('',#1201,.T.);
#1203=ADVANCED_FACE('F193',(#1199,#1202),#1196,.F.);
#1204=CARTESIAN_POINT('',(0.,0.,29.4));
#1205=DIRECTION('',(0.,0.,1.));
#1206=DIRECTION('',(1.,0.,0.));
#1207=AXIS2_PLACEMENT_3D('',#1204,#1205,#1206);
#1208=CONICAL_SURFACE('',#1207,7.,0.78539816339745);
#1209=ORIENTED_EDGE('',*,*,#979,.F.);
#1210=CARTESIAN_POINT('',(-1.83444761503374,6.75535357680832,29.4));
#1211=CARTESIAN_POINT('',(-1.79296647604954,6.82201631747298,29.4535030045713));
#1212=CARTESIAN_POINT('',(-1.75164692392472,6.88841937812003,29.5074441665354));
#1213=CARTESIAN_POINT('',(-1.66933105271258,7.02070604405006,29.6162027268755));
#1214=CARTESIAN_POINT('',(-1.62833473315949,7.08658965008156,29.6710201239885));
#1215=CARTESIAN_POINT('',(-1.5875,7.15221357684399,29.7262756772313));
#1216=B_SPLINE_CURVE_WITH_KNOTS('',3,(#1210,#1211,#1212,#1213,#1214,#1215),.UNSPECIFIED.,.F.,
.F.,(4,2,4),(0.,0.285020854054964,0.570041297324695),.UNSPECIFIED.);
#1217=CARTESIAN_POINT('',(-1.5875,7.15221357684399,29.7262756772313));
#1218=VERTEX_POINT('',#1217);
#1219=EDGE_CURVE('E233',#969,#1218,#1216,.T.);
#1220=ORIENTED_EDGE('',*,*,#1219,.T.);
#1221=CARTESIAN_POINT('',(-1.5875,16.0201778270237,38.4986413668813));
#1222=CARTESIAN_POINT('',(-1.5875,15.4370904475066,37.9184243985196));
#1223=CARTESIAN_POINT('',(-1.5875,14.8538754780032,37.338335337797));
#1224=CARTESIAN_POINT('',(-1.5875,13.6870022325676,36.17859913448));
#1225=CARTESIAN_POINT('',(-1.5875,13.103343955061,35.59895199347));
#1226=CARTESIAN_POINT('',(-1.5875,11.936200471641,34.4410838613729));
#1227=CARTESIAN_POINT('',(-1.5875,11.3527161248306,33.8628620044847));
#1228=CARTESIAN_POINT('',(-1.5875,10.1847781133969,32.7073994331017));
#1229=CARTESIAN_POINT('',(-1.5875,9.60032445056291,32.1301587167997));
#1230=CARTESIAN_POINT('',(-1.5875,8.67269807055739,31.216596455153));
#1231=CARTESIAN_POINT('',(-1.5875,8.33006753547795,30.8797246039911));
#1232=CARTESIAN_POINT('',(-1.5875,7.64379253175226,30.2066141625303));
#1233=CARTESIAN_POINT('',(-1.5875,7.30014758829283,29.8703760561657));
#1234=CARTESIAN_POINT('',(-1.5875,6.61151335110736,29.1989944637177));
#1235=CARTESIAN_POINT('',(-1.5875,6.26652356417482,28.863851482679));
#1236=CARTESIAN_POINT('',(-1.5875,5.74782650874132,28.362859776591));
#1237=CARTESIAN_POINT('',(-1.5875,5.57484304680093,28.1962619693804));
#1238=CARTESIAN_POINT('',(-1.5875,5.22825123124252,27.8637323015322));
#1239=CARTESIAN_POINT('',(-1.5875,5.0546429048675,27.697800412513));
#1240=CARTESIAN_POINT('',(-1.5875,4.68592865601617,27.3471649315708));
#1241=CARTESIAN_POINT('',(-1.5875,4.49071763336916,27.1625716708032));
#1242=CARTESIAN_POINT('',(-1.5875,4.09877309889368,26.7949375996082));
#1243=CARTESIAN_POINT('',(-1.5875,3.90203932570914,26.6118970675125));
#1244=CARTESIAN_POINT('',(-1.5875,3.50528928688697,26.2472059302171));
#1245=CARTESIAN_POINT('',(-1.5875,3.30526096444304,26.0655683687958));
#1246=CARTESIAN_POINT('',(-1.5875,3.00261440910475,25.7961408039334));
#1247=CARTESIAN_POINT('',(-1.5875,2.90132583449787,25.7068600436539));
#1248=CARTESIAN_POINT('',(-1.5875,2.69758990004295,25.5296360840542));
#1249=CARTESIAN_POINT('',(-1.5875,2.59514257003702,25.441692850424));
#1250=CARTESIAN_POINT('',(-1.5875,2.35788969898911,25.2415758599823));
#1251=CARTESIAN_POINT('',(-1.5875,2.22256236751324,25.1300139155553));
#1252=CARTESIAN_POINT('',(-1.5875,2.01659594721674,24.966146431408));
#1253=CARTESIAN_POINT('',(-1.5875,1.947379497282,24.9120550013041));
#1254=CARTESIAN_POINT('',(-1.5875,1.80775788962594,24.8054323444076));
#1255=CARTESIAN_POINT('',(-1.5875,1.73735281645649,24.7529010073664));
#1256=CARTESIAN_POINT('',(-1.5875,1.59559407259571,24.6502674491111));
#1257=CARTESIAN_POINT('',(-1.5875,1.5242515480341,24.6001499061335));
#1258=CARTESIAN_POINT('',(-1.5875,1.37970871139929,24.5025945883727));
#1259=CARTESIAN_POINT('',(-1.5875,1.30650780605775,24.4551576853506));
#1260=CARTESIAN_POINT('',(-1.5875,1.15804240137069,24.364124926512));
#1261=CARTESIAN_POINT('',(-1.5875,1.08278485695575,24.3205178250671));
#1262=CARTESIAN_POINT('',(-1.5875,0.929523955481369,24.2384729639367));
#1263=CARTESIAN_POINT('',(-1.5875,0.851523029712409,24.2000307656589));
#1264=CARTESIAN_POINT('',(-1.5875,0.722181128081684,24.1434759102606));
#1265=CARTESIAN_POINT('',(-1.5875,0.671813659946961,24.1231461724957));
#1266=CARTESIAN_POINT('',(-1.5875,0.569779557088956,24.0859854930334));
#1267=CARTESIAN_POINT('',(-1.5875,0.518112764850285,24.0691549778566));
#1268=CARTESIAN_POINT('',(-1.5875,0.413819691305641,24.0397909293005));
#1269=CARTESIAN_POINT('',(-1.5875,0.361199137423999,24.0272373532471));
#1270=CARTESIAN_POINT('',(-1.5875,0.255032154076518,24.0070115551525));
#1271=CARTESIAN_POINT('',(-1.5875,0.201486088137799,23.9993374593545));
#1272=CARTESIAN_POINT('',(-1.5875,0.0931887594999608,23.9893076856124));
#1273=CARTESIAN_POINT('',(-1.5875,0.038430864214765,23.9870220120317));
#1274=CARTESIAN_POINT('',(-1.5875,-0.0710230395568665,23.9881452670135));
#1275=CARTESIAN_POINT('',(-1.5875,-0.125719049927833,23.9915540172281));
#1276=CARTESIAN_POINT('',(-1.5875,-0.234638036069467,24.0038304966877));
#1277=CARTESIAN_POINT('',(-1.5875,-0.288859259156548,24.0127134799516));
#1278=CARTESIAN_POINT('',(-1.5875,-0.396265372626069,24.0353660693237));
#1279=CARTESIAN_POINT('',(-1.5875,-0.449449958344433,24.0491370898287));
#1280=CARTESIAN_POINT('',(-1.5875,-0.57665543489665,24.0874886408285));
#1281=CARTESIAN_POINT('',(-1.5875,-0.650035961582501,24.1141796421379));
#1282=CARTESIAN_POINT('',(-1.5875,-0.794174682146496,24.1738526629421));
#1283=CARTESIAN_POINT('',(-1.5875,-0.864931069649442,24.2068389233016));
#1284=CARTESIAN_POINT('',(-1.5875,-1.00443258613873,24.2776074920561));
#1285=CARTESIAN_POINT('',(-1.5875,-1.07316552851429,24.3154135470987));
#1286=CARTESIAN_POINT('',(-1.5875,-1.17472772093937,24.3746873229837));
#1287=CARTESIAN_POINT('',(-1.5875,-1.20832064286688,24.3948694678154));
#1288=CARTESIAN_POINT('',(-1.5875,-1.27504632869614,24.4359786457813));
#1289=CARTESIAN_POINT('',(-1.5875,-1.30817911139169,24.4569056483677));
#1290=CARTESIAN_POINT('',(-1.5875,-1.41890925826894,24.5283599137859));
#1291=CARTESIAN_POINT('',(-1.5875,-1.49555985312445,24.5803554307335));
#1292=CARTESIAN_POINT('',(-1.5875,-1.64705118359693,24.6869288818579));
#1293=CARTESIAN_POINT('',(-1.5875,-1.7218914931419,24.7415074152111));
#1294=CARTESIAN_POINT('',(-1.5875,-1.87018633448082,24.8526190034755));
#1295=CARTESIAN_POINT('',(-1.5875,-1.94363982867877,24.9091534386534));
#1296=CARTESIAN_POINT('',(-1.5875,-2.08939971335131,25.0236852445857));
#1297=CARTESIAN_POINT('',(-1.5875,-2.16170603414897,25.0816827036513));
#1298=CARTESIAN_POINT('',(-1.5875,-2.37760541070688,25.2576467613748));
#1299=CARTESIAN_POINT('',(-1.5875,-2.51981579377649,25.3773075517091));
#1300=CARTESIAN_POINT('',(-1.5875,-2.80171931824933,25.6194142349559));
#1301=CARTESIAN_POINT('',(-1.5875,-2.94141349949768,25.74185892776));
#1302=CARTESIAN_POINT('',(-1.5875,-3.21965159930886,25.9891834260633));
#1303=CARTESIAN_POINT('',(-1.5875,-3.35818846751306,26.1140711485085));
#1304=CARTESIAN_POINT('',(-1.5875,-3.63402502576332,26.3652305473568));
#1305=CARTESIAN_POINT('',(-1.5875,-3.77132458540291,26.4915023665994));
#1306=CARTESIAN_POINT('',(-1.5875,-4.04476940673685,26.7448446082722));
#1307=CARTESIAN_POINT('',(-1.5875,-4.18091618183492,26.8719133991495));
#1308=CARTESIAN_POINT('',(-1.5875,-4.45249362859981,27.1268033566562));
#1309=CARTESIAN_POINT('',(-1.5875,-4.58792432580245,27.2546244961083));
#1310=CARTESIAN_POINT('',(-1.5875,-4.98651374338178,27.6324347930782));
#1311=CARTESIAN_POINT('',(-1.5875,-5.24890460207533,27.8832336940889));
#1312=CARTESIAN_POINT('',(-1.5875,-5.77234478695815,28.3862285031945));
#1313=CARTESIAN_POINT('',(-1.5875,-6.03339410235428,28.638424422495));
#1314=CARTESIAN_POINT('',(-1.5875,-6.55457562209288,29.1437790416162));
#1315=CARTESIAN_POINT('',(-1.5875,-6.81470779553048,29.3969377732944));
#1316=CARTESIAN_POINT('',(-1.5875,-7.3343092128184,29.9039348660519));
#1317=CARTESIAN_POINT('',(-1.5875,-7.59377845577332,30.1577732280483));
#1318=CARTESIAN_POINT('',(-1.5875,-8.37187525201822,30.920431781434));
#1319=CARTESIAN_POINT('',(-1.5875,-8.88977719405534,31.4299920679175));
#1320=CARTESIAN_POINT('',(-1.5875,-9.9244437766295,32.4502473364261));
#1321=CARTESIAN_POINT('',(-1.5875,-10.4412084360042,32.9609422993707));
#1322=CARTESIAN_POINT('',(-1.5875,-11.4577606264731,33.9669917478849));
#1323=CARTESIAN_POINT('',(-1.5875,-11.9575707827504,34.4623233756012));
#1324=CARTESIAN_POINT('',(-1.5875,-12.95672409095,35.453462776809));
#1325=CARTESIAN_POINT('',(-1.5875,-13.4560672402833,35.9492705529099));
#1326=CARTESIAN_POINT('',(-1.5875,-14.4539809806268,36.9407884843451));
#1327=CARTESIAN_POINT('',(-1.5875,-14.9525518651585,37.4364983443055));
#1328=CARTESIAN_POINT('',(-1.5875,-15.9494376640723,38.4281693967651));
#1329=CARTESIAN_POINT('',(-1.5875,-16.4477525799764,38.9241305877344));
#1330=CARTESIAN_POINT('',(-1.5875,-16.9459817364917,39.4201778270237));
#1331=B_SPLINE_CURVE_WITH_KNOTS('',3,(#1221,#1222,#1223,#1224,#1225,#1226,#1227,#1228,#1229,
#1230,#1231,#1232,#1233,#1234,#1235,#1236,#1237,#1238,#1239,#1240,#1241,#1242,#1243,#1244,#1245,
#1246,#1247,#1248,#1249,#1250,#1251,#1252,#1253,#1254,#1255,#1256,#1257,#1258,#1259,#1260,#1261,
#1262,#1263,#1264,#1265,#1266,#1267,#1268,#1269,#1270,#1271,#1272,#1273,#1274,#1275,#1276,#1277,
#1278,#1279,#1280,#1281,#1282,#1283,#1284,#1285,#1286,#1287,#1288,#1289,#1290,#1291,#1292,#1293,
#1294,#1295,#1296,#1297,#1298,#1299,#1300,#1301,#1302,#1303,#1304,#1305,#1306,#1307,#1308,#1309,
#1310,#1311,#1312,#1313,#1314,#1315,#1316,#1317,#1318,#1319,#1320,#1321,#1322,#1323,#1324,#1325,
#1326,#1327,#1328,#1329,#1330),.UNSPECIFIED.,.F.,.F.,(4,2,2,2,2,2,2,2,2,2,2,2,2,2,2,2,2,2,2,2,2,
2,2,2,2,2,2,2,2,2,2,2,2,2,2,2,2,2,2,2,2,2,2,2,2,2,2,2,2,2,2,2,2,2,4),(0.,2.46774902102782,
4.93550684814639,7.39988256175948,9.86425373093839,11.3057467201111,12.7480804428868,
14.1910052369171,14.9114919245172,15.6319475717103,16.4379423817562,17.2440787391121,
18.0546161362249,18.4596667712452,18.8647069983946,19.3907760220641,19.6542960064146,
19.9177973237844,20.1793130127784,20.440913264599,20.7017177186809,20.9622965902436,
21.1251411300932,21.2880055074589,21.4500958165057,21.6121238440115,21.7762455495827,
21.9403621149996,22.1049380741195,22.2695616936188,22.5033952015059,22.7373867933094,
22.9725793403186,23.090140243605,23.2076963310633,23.4854786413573,23.7633257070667,
24.0413730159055,24.3194371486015,24.8769356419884,25.434198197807,25.993742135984,
26.553344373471,27.1120370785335,27.6707097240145,28.7596177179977,29.8485344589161,
30.9374875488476,32.0264421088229,34.2060867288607,36.3856949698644,38.4967303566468,
40.6077773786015,42.7169739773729,44.8261578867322),.UNSPECIFIED.);
#1332=EDGE_CURVE('E197',#735,#1218,#1331,.T.);
#1333=ORIENTED_EDGE('',*,*,#1332,.F.);
#1334=ORIENTED_EDGE('',*,*,#736,.F.);
#1335=CARTESIAN_POINT('',(1.5875,-16.9459817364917,39.4201778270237));
#1336=CARTESIAN_POINT('',(1.5875,-16.3379280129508,38.8147989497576));
#1337=CARTESIAN_POINT('',(1.5875,-15.7297552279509,38.2095394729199));
#1338=CARTESIAN_POINT('',(1.5875,-14.5129540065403,36.9993751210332));
#1339=CARTESIAN_POINT('',(1.5875,-13.904325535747,36.3944702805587));
#1340=CARTESIAN_POINT('',(1.5875,-12.6852676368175,35.1840115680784));
#1341=CARTESIAN_POINT('',(1.5875,-12.0748370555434,34.5784588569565));
#1342=CARTESIAN_POINT('',(1.5875,-10.8531357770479,33.3683025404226));
#1343=CARTESIAN_POINT('',(1.5875,-10.2418651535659,32.7636988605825));
#1344=CARTESIAN_POINT('',(1.5875,-9.05794051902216,31.5955216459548));
#1345=CARTESIAN_POINT('',(1.5875,-8.48537927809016,31.0318542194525));
#1346=CARTESIAN_POINT('',(1.5875,-7.62473679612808,30.1880458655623));
#1347=CARTESIAN_POINT('',(1.5875,-7.33751994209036,29.9070236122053));
#1348=CARTESIAN_POINT('',(1.5875,-6.7622739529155,29.345824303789));
#1349=CARTESIAN_POINT('',(1.5875,-6.47424483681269,29.0656472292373));
#1350=CARTESIAN_POINT('',(1.5875,-5.8973394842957,28.5068514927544));
#1351=CARTESIAN_POINT('',(1.5875,-5.60846465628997,28.2282313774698));
#1352=CARTESIAN_POINT('',(1.5875,-5.02888508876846,27.6728422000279));
#1353=CARTESIAN_POINT('',(1.5875,-4.73818018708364,27.3960733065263));
#1354=CARTESIAN_POINT('',(1.5875,-4.29993509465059,26.9833649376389));
#1355=CARTESIAN_POINT('',(1.5875,-4.15351992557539,26.8462316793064));
#1356=CARTESIAN_POINT('',(1.5875,-3.85968155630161,26.5730503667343));
#1357=CARTESIAN_POINT('',(1.5875,-3.71225836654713,26.4370023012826));
#1358=CARTESIAN_POINT('',(1.5875,-3.41605911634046,26.1664286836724));
#1359=CARTESIAN_POINT('',(1.5875,-3.26728325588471,26.0319029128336));
#1360=CARTESIAN_POINT('',(1.5875,-2.96780248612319,25.7650192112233));
#1361=CARTESIAN_POINT('',(1.5875,-2.81709768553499,25.6326611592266));
#1362=CARTESIAN_POINT('',(1.5875,-2.62241117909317,25.4654089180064));
#1363=CARTESIAN_POINT('',(1.5875,-2.57974585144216,25.4289818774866));
#1364=CARTESIAN_POINT('',(1.5875,-2.49415921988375,25.3564285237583));
#1365=CARTESIAN_POINT('',(1.5875,-2.45123791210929,25.3203022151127));
#1366=CARTESIAN_POINT('',(1.5875,-2.32203797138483,25.21243005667));
#1367=CARTESIAN_POINT('',(1.5875,-2.23532969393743,25.1411964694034));
#1368=CARTESIAN_POINT('',(1.5875,-2.05932687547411,24.999655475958));
#1369=CARTESIAN_POINT('',(1.5875,-1.97001345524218,24.9293714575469));
#1370=CARTESIAN_POINT('',(1.5875,-1.78942055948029,24.7913977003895));
#1371=CARTESIAN_POINT('',(1.5875,-1.69814148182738,24.7237074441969));
#1372=CARTESIAN_POINT('',(1.5875,-1.51147255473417,24.5909626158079));
#1373=CARTESIAN_POINT('',(1.5875,-1.41604045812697,24.5259669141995));
#1374=CARTESIAN_POINT('',(1.5875,-1.22135824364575,24.4015622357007));
#1375=CARTESIAN_POINT('',(1.5875,-1.12210327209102,24.3421607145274));
#1376=CARTESIAN_POINT('',(1.5875,-0.920144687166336,24.2329420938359));
#1377=CARTESIAN_POINT('',(1.5875,-0.81750861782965,24.1830026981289));
#1378=CARTESIAN_POINT('',(1.5875,-0.606694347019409,24.096793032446));
#1379=CARTESIAN_POINT('',(1.5875,-0.498536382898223,24.0604764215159));
#1380=CARTESIAN_POINT('',(1.5875,-0.336087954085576,24.0219003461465));
#1381=CARTESIAN_POINT('',(1.5875,-0.283654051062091,24.0117937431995));
#1382=CARTESIAN_POINT('',(1.5875,-0.178048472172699,23.9966005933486));
#1383=CARTESIAN_POINT('',(1.5875,-0.12487684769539,23.9915136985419));
#1384=CARTESIAN_POINT('',(1.5875,-0.0183779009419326,23.9867164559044));
#1385=CARTESIAN_POINT('',(1.5875,0.034949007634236,23.9869970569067));
#1386=CARTESIAN_POINT('',(1.5875,0.141306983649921,23.9928914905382));
#1387=CARTESIAN_POINT('',(1.5875,0.194338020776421,23.9985058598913));
#1388=CARTESIAN_POINT('',(1.5875,0.299113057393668,24.0146108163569));
#1389=CARTESIAN_POINT('',(1.5875,0.350864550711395,24.0250535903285));
#1390=CARTESIAN_POINT('',(1.5875,0.453308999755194,24.0502051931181));
#1391=CARTESIAN_POINT('',(1.5875,0.504001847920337,24.0649144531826));
#1392=CARTESIAN_POINT('',(1.5875,0.60442030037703,24.0980046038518));
#1393=CARTESIAN_POINT('',(1.5875,0.654140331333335,24.1164021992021));
#1394=CARTESIAN_POINT('',(1.5875,0.752345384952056,24.1561799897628));
#1395=CARTESIAN_POINT('',(1.5875,0.800830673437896,24.177559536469));
#1396=CARTESIAN_POINT('',(1.5875,0.950438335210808,24.2480823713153));
#1397=CARTESIAN_POINT('',(1.5875,1.04956184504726,24.3014548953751));
#1398=CARTESIAN_POINT('',(1.5875,1.24376503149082,24.4151728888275));
#1399=CARTESIAN_POINT('',(1.5875,1.33883912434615,24.4755275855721));
#1400=CARTESIAN_POINT('',(1.5875,1.5262612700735,24.6010861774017));
#1401=CARTESIAN_POINT('',(1.5875,1.61859674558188,24.6663086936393));
#1402=CARTESIAN_POINT('',(1.5875,1.80087294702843,24.7998886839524));
#1403=CARTESIAN_POINT('',(1.5875,1.89081492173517,24.868244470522));
#1404=CARTESIAN_POINT('',(1.5875,2.06965001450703,25.007768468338));
#1405=CARTESIAN_POINT('',(1.5875,2.15852886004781,25.0789548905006));
#1406=CARTESIAN_POINT('',(1.5875,2.33491835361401,25.2230168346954));
#1407=CARTESIAN_POINT('',(1.5875,2.42242884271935,25.2958925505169));
#1408=CARTESIAN_POINT('',(1.5875,2.68296934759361,25.5160533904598));
#1409=CARTESIAN_POINT('',(1.5875,2.85442207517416,25.6652018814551));
#1410=CARTESIAN_POINT('',(1.5875,3.18260972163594,25.9558195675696));
#1411=CARTESIAN_POINT('',(1.5875,3.33952705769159,26.0970845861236));
#1412=CARTESIAN_POINT('',(1.5875,3.65184547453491,26.3814513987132));
#1413=CARTESIAN_POINT('',(1.5875,3.80724567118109,26.5245541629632));
#1414=CARTESIAN_POINT('',(1.5875,4.11612407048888,26.8112769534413));
#1415=CARTESIAN_POINT('',(1.5875,4.2696079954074,26.954890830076));
#1416=CARTESIAN_POINT('',(1.5875,4.57570709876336,27.2429931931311));
#1417=CARTESIAN_POINT('',(1.5875,4.72832240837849,27.3874815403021));
#1418=CARTESIAN_POINT('',(1.5875,5.05464247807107,27.6977982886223));
#1419=CARTESIAN_POINT('',(1.5875,5.2282491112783,27.8637297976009));
#1420=CARTESIAN_POINT('',(1.5875,5.57483833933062,28.1962579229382));
#1421=CARTESIAN_POINT('',(1.5875,5.74782090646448,28.3628545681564));
#1422=CARTESIAN_POINT('',(1.5875,6.26651938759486,28.8638470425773));
#1423=CARTESIAN_POINT('',(1.5875,6.61151136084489,29.1989921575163));
#1424=CARTESIAN_POINT('',(1.5875,7.30011347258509,29.8703431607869));
#1425=CARTESIAN_POINT('',(1.5875,7.64372423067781,30.2065484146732));
#1426=CARTESIAN_POINT('',(1.5875,8.33000048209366,30.8796575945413));
#1427=CARTESIAN_POINT('',(1.5875,8.67266628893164,31.2165612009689));
#1428=CARTESIAN_POINT('',(1.5875,9.29323161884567,31.8277250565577));
#1429=CARTESIAN_POINT('',(1.5875,9.57122815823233,32.1018868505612));
#1430=CARTESIAN_POINT('',(1.5875,10.1269707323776,32.6505482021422));
#1431=CARTESIAN_POINT('',(1.5875,10.4047167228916,32.9250478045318));
#1432=CARTESIAN_POINT('',(1.5875,11.1280426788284,33.6405151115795));
#1433=CARTESIAN_POINT('',(1.5875,11.5734422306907,34.0816651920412));
#1434=CARTESIAN_POINT('',(1.5875,12.4638263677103,34.9643841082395));
#1435=CARTESIAN_POINT('',(1.5875,12.9088109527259,35.4059529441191));
#1436=CARTESIAN_POINT('',(1.5875,13.798323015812,36.2892442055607));
#1437=CARTESIAN_POINT('',(1.5875,14.2428505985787,36.7309665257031));
#1438=CARTESIAN_POINT('',(1.5875,15.1316719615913,37.6146456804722));
#1439=CARTESIAN_POINT('',(1.5875,15.5759657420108,38.0566025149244));
#1440=CARTESIAN_POINT('',(1.5875,16.0201778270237,38.4986413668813));
#1441=B_SPLINE_CURVE_WITH_KNOTS('',3,(#1335,#1336,#1337,#1338,#1339,#1340,#1341,#1342,#1343,
#1344,#1345,#1346,#1347,#1348,#1349,#1350,#1351,#1352,#1353,#1354,#1355,#1356,#1357,#1358,#1359,
#1360,#1361,#1362,#1363,#1364,#1365,#1366,#1367,#1368,#1369,#1370,#1371,#1372,#1373,#1374,#1375,
#1376,#1377,#1378,#1379,#1380,#1381,#1382,#1383,#1384,#1385,#1386,#1387,#1388,#1389,#1390,#1391,
#1392,#1393,#1394,#1395,#1396,#1397,#1398,#1399,#1400,#1401,#1402,#1403,#1404,#1405,#1406,#1407,
#1408,#1409,#1410,#1411,#1412,#1413,#1414,#1415,#1416,#1417,#1418,#1419,#1420,#1421,#1422,#1423,
#1424,#1425,#1426,#1427,#1428,#1429,#1430,#1431,#1432,#1433,#1434,#1435,#1436,#1437,#1438,#1439,
#1440),.UNSPECIFIED.,.F.,.F.,(4,2,2,2,2,2,2,2,2,2,2,2,2,2,2,2,2,2,2,2,2,2,2,2,2,2,2,2,2,2,2,2,2,
2,2,2,2,2,2,2,2,2,2,2,2,2,2,2,2,2,2,2,4),(0.,2.57408569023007,5.14839051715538,7.72790070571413,
10.307197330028,12.7175715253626,13.9230592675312,15.1285189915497,16.332550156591,
17.5366895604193,18.1385051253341,18.7403144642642,19.3420362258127,19.9437242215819,
20.1120243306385,20.2803269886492,20.6169575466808,20.9578800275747,21.298734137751,
21.6449971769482,21.9917153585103,22.3335901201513,22.6742911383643,22.8342819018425,
22.994261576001,23.1539715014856,23.3136974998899,23.4718746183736,23.6300677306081,
23.7889941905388,23.9478861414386,24.2851123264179,24.6227893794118,24.9618318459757,
25.3006938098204,25.6422837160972,25.9839130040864,26.6655853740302,27.2989830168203,
27.9327300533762,28.5633130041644,29.1937980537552,29.9142488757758,30.6347313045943,
32.077665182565,33.5198567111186,34.9614918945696,36.1328246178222,37.3043344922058,
39.1850114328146,41.0656890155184,42.9457182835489,44.8257461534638),.UNSPECIFIED.);
#1442=CARTESIAN_POINT('',(1.5875,7.15221357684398,29.7262756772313));
#1443=VERTEX_POINT('',#1442);
#1444=EDGE_CURVE('E205',#1443,#724,#1441,.T.);
#1445=ORIENTED_EDGE('',*,*,#1444,.F.);
#1446=CARTESIAN_POINT('',(1.5875,7.15221357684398,29.7262756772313));
#1447=CARTESIAN_POINT('',(1.62833473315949,7.08658965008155,29.6710201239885));
#1448=CARTESIAN_POINT('',(1.66933105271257,7.02070604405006,29.6162027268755));
#1449=CARTESIAN_POINT('',(1.75164692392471,6.88841937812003,29.5074441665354));
#1450=CARTESIAN_POINT('',(1.79296647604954,6.82201631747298,29.4535030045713));
#1451=CARTESIAN_POINT('',(1.83444761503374,6.75535357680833,29.4));
#1452=B_SPLINE_CURVE_WITH_KNOTS('',3,(#1446,#1447,#1448,#1449,#1450,#1451),.UNSPECIFIED.,.F.,
.F.,(4,2,4),(0.,0.285020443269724,0.57004129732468),.UNSPECIFIED.);
#1453=EDGE_CURVE('E228',#1443,#978,#1452,.T.);
#1454=ORIENTED_EDGE('',*,*,#1453,.T.);
#1455=EDGE_LOOP('',(#1209,#1220,#1333,#1334,#1445,#1454));
#1456=FACE_BOUND('',#1455,.T.);
#1457=ADVANCED_FACE('F212',(#1456),#1208,.F.);
#1458=CARTESIAN_POINT('',(1.5875,8.5875,31.5));
#1459=DIRECTION('',(1.,0.,0.));
#1460=DIRECTION('',(0.,0.,-1.));
#1461=AXIS2_PLACEMENT_3D('',#1458,#1459,#1460);
#1462=PLANE('',#1461);
#1463=ORIENTED_EDGE('',*,*,#1182,.F.);
#1464=DIRECTION('',(0.,0.,1.));
#1465=VECTOR('',#1464,1.);
#1466=CARTESIAN_POINT('',(1.5875,7.15221357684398,29.4));
#1467=LINE('',#1466,#1465);
#1468=EDGE_CURVE('E11',#1173,#1443,#1467,.T.);
#1469=ORIENTED_EDGE('',*,*,#1468,.T.);
#1470=ORIENTED_EDGE('',*,*,#1444,.T.);
#1471=ORIENTED_EDGE('',*,*,#727,.T.);
#1472=DIRECTION('',(0.,0.,1.));
#1473=VECTOR('',#1472,1.);
#1474=CARTESIAN_POINT('',(1.5875,8.5875,31.5));
#1475=LINE('',#1474,#1473);
#1476=EDGE_CURVE('E152',#1181,#726,#1475,.T.);
#1477=ORIENTED_EDGE('',*,*,#1476,.F.);
#1478=EDGE_LOOP('',(#1463,#1469,#1470,#1471,#1477));
#1479=FACE_BOUND('',#1478,.T.);
#1480=ADVANCED_FACE('F191',(#1479),#1462,.F.);
#1481=CARTESIAN_POINT('',(-1.5875,8.5875,31.5));
#1482=DIRECTION('',(-1.,0.,0.));
#1483=DIRECTION('',(0.,0.,1.));
#1484=AXIS2_PLACEMENT_3D('',#1481,#1482,#1483);
#1485=PLANE('',#1484);
#1486=ORIENTED_EDGE('',*,*,#1332,.T.);
#1487=DIRECTION('',(0.,0.,-1.));
#1488=VECTOR('',#1487,1.);
#1489=CARTESIAN_POINT('',(-1.5875,7.15221357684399,24.4998263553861));
#1490=LINE('',#1489,#1488);
#1491=EDGE_CURVE('E562',#1218,#1130,#1490,.T.);
#1492=ORIENTED_EDGE('',*,*,#1491,.T.);
#1493=ORIENTED_EDGE('',*,*,#1131,.F.);
#1494=DIRECTION('',(0.,0.,-1.));
#1495=VECTOR('',#1494,1.);
#1496=CARTESIAN_POINT('',(-1.5875,8.5875,31.5));
#1497=LINE('',#1496,#1495);
#1498=EDGE_CURVE('E143',#743,#1128,#1497,.T.);
#1499=ORIENTED_EDGE('',*,*,#1498,.F.);
#1500=ORIENTED_EDGE('',*,*,#744,.T.);
#1501=EDGE_LOOP('',(#1486,#1492,#1493,#1499,#1500));
#1502=FACE_BOUND('',#1501,.T.);
#1503=ADVANCED_FACE('F186',(#1502),#1485,.F.);
#1504=CARTESIAN_POINT('',(0.,8.5875,31.5));
#1505=DIRECTION('',(0.,-1.,0.));
#1506=DIRECTION('',(0.,0.,-1.));
#1507=AXIS2_PLACEMENT_3D('',#1504,#1505,#1506);
#1508=PLANE('',#1507);
#1509=ORIENTED_EDGE('',*,*,#1498,.T.);
#1510=ORIENTED_EDGE('',*,*,#1184,.T.);
#1511=ORIENTED_EDGE('',*,*,#1476,.T.);
#1512=ORIENTED_EDGE('',*,*,#750,.F.);
#1513=EDGE_LOOP('',(#1509,#1510,#1511,#1512));
#1514=FACE_BOUND('',#1513,.T.);
#1515=ADVANCED_FACE('F190',(#1514),#1508,.T.);
#1516=ORIENTED_EDGE('',*,*,#1157,.T.);
#1517=CARTESIAN_POINT('',(-1.5875,8.5875,21.5));
#1518=VERTEX_POINT('',#1517);
#1519=EDGE_CURVE('E136',#1147,#1518,#1497,.T.);
#1520=ORIENTED_EDGE('',*,*,#1519,.T.);
#1521=CARTESIAN_POINT('',(0.,8.5875,21.5));
#1522=DIRECTION('',(0.,-1.,0.));
#1523=DIRECTION('',(0.,0.,-1.));
#1524=AXIS2_PLACEMENT_3D('',#1521,#1522,#1523);
#1525=CIRCLE('',#1524,1.5875);
#1526=CARTESIAN_POINT('',(1.5875,8.5875,21.5));
#1527=VERTEX_POINT('',#1526);
#1528=EDGE_CURVE('E139',#1518,#1527,#1525,.T.);
#1529=ORIENTED_EDGE('',*,*,#1528,.T.);
#1530=EDGE_CURVE('E149',#1527,#1156,#1475,.T.);
#1531=ORIENTED_EDGE('',*,*,#1530,.T.);
#1532=EDGE_LOOP('',(#1516,#1520,#1529,#1531));
#1533=FACE_BOUND('',#1532,.T.);
#1534=ADVANCED_FACE('F137',(#1533),#1508,.T.);
#1535=DIRECTION('',(0.,-1.,0.));
#1536=VECTOR('',#1535,1.);
#1537=CARTESIAN_POINT('',(1.5875,8.5875,21.5));
#1538=LINE('',#1537,#1536);
#1539=CARTESIAN_POINT('',(1.5875,7.15221357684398,21.5));
#1540=VERTEX_POINT('',#1539);
#1541=EDGE_CURVE('E148',#1527,#1540,#1538,.T.);
#1542=ORIENTED_EDGE('',*,*,#1541,.T.);
#1543=DIRECTION('',(0.,0.,1.));
#1544=VECTOR('',#1543,1.);
#1545=CARTESIAN_POINT('',(1.5875,7.15221357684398,23.6001736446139));
#1546=LINE('',#1545,#1544);
#1547=EDGE_CURVE('E45',#1540,#1164,#1546,.T.);
#1548=ORIENTED_EDGE('',*,*,#1547,.T.);
#1549=ORIENTED_EDGE('',*,*,#1165,.F.);
#1550=ORIENTED_EDGE('',*,*,#1530,.F.);
#1551=EDGE_LOOP('',(#1542,#1548,#1549,#1550));
#1552=FACE_BOUND('',#1551,.T.);
#1553=ADVANCED_FACE('F183',(#1552),#1462,.F.);
#1554=ORIENTED_EDGE('',*,*,#1148,.F.);
#1555=DIRECTION('',(0.,0.,-1.));
#1556=VECTOR('',#1555,1.);
#1557=CARTESIAN_POINT('',(-1.5875,7.15221357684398,21.5));
#1558=LINE('',#1557,#1556);
#1559=CARTESIAN_POINT('',(-1.5875,7.15221357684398,21.5));
#1560=VERTEX_POINT('',#1559);
#1561=EDGE_CURVE('E62',#1139,#1560,#1558,.T.);
#1562=ORIENTED_EDGE('',*,*,#1561,.T.);
#1563=DIRECTION('',(0.,-1.,0.));
#1564=VECTOR('',#1563,1.);
#1565=CARTESIAN_POINT('',(-1.5875,8.5875,21.5));
#1566=LINE('',#1565,#1564);
#1567=EDGE_CURVE('E146',#1518,#1560,#1566,.T.);
#1568=ORIENTED_EDGE('',*,*,#1567,.F.);
#1569=ORIENTED_EDGE('',*,*,#1519,.F.);
#1570=EDGE_LOOP('',(#1554,#1562,#1568,#1569));
#1571=FACE_BOUND('',#1570,.T.);
#1572=ADVANCED_FACE('F147',(#1571),#1485,.F.);
#1573=CARTESIAN_POINT('',(0.,8.5875,21.5));
#1574=DIRECTION('',(0.,-1.,0.));
#1575=DIRECTION('',(0.,0.,-1.));
#1576=AXIS2_PLACEMENT_3D('',#1573,#1574,#1575);
#1577=CYLINDRICAL_SURFACE('',#1576,1.5875);
#1578=ORIENTED_EDGE('',*,*,#1567,.T.);
#1579=CARTESIAN_POINT('',(1.5875,7.15221357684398,21.5));
#1580=CARTESIAN_POINT('',(1.58902400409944,7.15047343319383,21.0814565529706));
#1581=CARTESIAN_POINT('',(1.41479420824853,7.21414592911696,20.6700747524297));
#1582=CARTESIAN_POINT('',(0.83032639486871,7.35159016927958,20.0849177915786));
#1583=CARTESIAN_POINT('',(0.419761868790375,7.41118810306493,19.9125713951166));
#1584=CARTESIAN_POINT('',(-0.416867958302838,7.4112761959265,19.9124299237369));
#1585=CARTESIAN_POINT('',(-0.829134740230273,7.35172857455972,20.084032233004));
#1586=CARTESIAN_POINT('',(-1.4150351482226,7.2142268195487,20.6700099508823));
#1587=CARTESIAN_POINT('',(-1.58873442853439,7.15059829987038,21.0777889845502));
#1588=CARTESIAN_POINT('',(-1.5875,7.15221357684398,21.5));
#1589=B_SPLINE_CURVE_WITH_KNOTS('',3,(#1579,#1580,#1581,#1582,#1583,#1584,#1585,#1586,#1587,
#1588),.UNSPECIFIED.,.F.,.F.,(4,2,2,2,4),(0.,0.00152425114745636,0.00304850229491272,
0.00457275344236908,0.00609700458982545),.UNSPECIFIED.);
#1590=EDGE_CURVE('E53',#1560,#1540,#1589,.F.);
#1591=ORIENTED_EDGE('',*,*,#1590,.T.);
#1592=ORIENTED_EDGE('',*,*,#1541,.F.);
#1593=ORIENTED_EDGE('',*,*,#1528,.F.);
#1594=EDGE_LOOP('',(#1578,#1591,#1592,#1593));
#1595=FACE_BOUND('',#1594,.T.);
#1596=ADVANCED_FACE('F151',(#1595),#1577,.F.);
#1597=CARTESIAN_POINT('',(1.5875,7.15221357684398,30.4));
#1598=DIRECTION('',(-0.849044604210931,-0.528321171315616,0.));
#1599=DIRECTION('',(0.528321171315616,-0.849044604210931,0.));
#1600=AXIS2_PLACEMENT_3D('',#1597,#1598,#1599);
#1601=PLANE('',#1600);
#1602=ORIENTED_EDGE('',*,*,#1453,.F.);
#1603=ORIENTED_EDGE('',*,*,#1468,.F.);
#1604=CARTESIAN_POINT('',(1.83461165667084,6.75521037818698,24.5595079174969));
#1605=CARTESIAN_POINT('',(1.82438089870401,6.77203941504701,24.5573302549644));
#1606=CARTESIAN_POINT('',(1.81415600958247,6.78886742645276,24.5551170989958));
#1607=CARTESIAN_POINT('',(1.79371529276,6.82252611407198,24.5506192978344));
#1608=CARTESIAN_POINT('',(1.78349946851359,6.83935678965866,24.5483346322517));
#1609=CARTESIAN_POINT('',(1.7630770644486,6.87302082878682,24.5436938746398));
#1610=CARTESIAN_POINT('',(1.75287048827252,6.88985419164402,24.5413377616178));
#1611=CARTESIAN_POINT('',(1.73246676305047,6.92352362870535,24.5365541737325));
#1612=CARTESIAN_POINT('',(1.72226961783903,6.9403597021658,24.5341266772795));
#1613=CARTESIAN_POINT('',(1.70188493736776,6.9740345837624,24.5292003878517));
#1614=CARTESIAN_POINT('',(1.69169740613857,6.9908733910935,24.5267015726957));
#1615=CARTESIAN_POINT('',(1.67133213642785,7.02455376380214,24.5216327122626));
#1616=CARTESIAN_POINT('',(1.66115440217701,7.04139532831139,24.5190626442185));
#1617=CARTESIAN_POINT('',(1.64080890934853,7.07508123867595,24.5138513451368));
#1618=CARTESIAN_POINT('',(1.63064115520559,7.09192558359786,24.5112100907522));
#1619=CARTESIAN_POINT('',(1.61031580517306,7.12561707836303,24.5058564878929));
#1620=CARTESIAN_POINT('',(1.60015821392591,7.14246422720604,24.5031441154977));
#1621=CARTESIAN_POINT('',(1.59000756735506,7.1593098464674,24.5003967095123));
#1622=B_SPLINE_CURVE_WITH_KNOTS('',3,(#1604,#1605,#1606,#1607,#1608,#1609,#1610,#1611,#1612,
#1613,#1614,#1615,#1616,#1617,#1618,#1619,#1620,#1621),.UNSPECIFIED.,.F.,.F.,(4,2,2,2,2,2,2,2,
4),(0.,0.0594444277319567,0.118905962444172,0.178385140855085,0.237882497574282,
0.297398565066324,0.356933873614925,0.416488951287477,0.476064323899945),.UNSPECIFIED.);
#1623=EDGE_CURVE('E630',#986,#1173,#1622,.T.);
#1624=ORIENTED_EDGE('',*,*,#1623,.F.);
#1625=ORIENTED_EDGE('',*,*,#987,.F.);
#1626=EDGE_LOOP('',(#1602,#1603,#1624,#1625));
#1627=FACE_BOUND('',#1626,.T.);
#1628=ADVANCED_FACE('F36',(#1627),#1601,.T.);
#1629=CARTESIAN_POINT('',(1.57451954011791,7.16762317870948,23.5566560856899));
#1630=CARTESIAN_POINT('',(1.67452762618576,7.13430031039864,23.8728725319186));
#1631=CARTESIAN_POINT('',(1.67548909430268,7.13397720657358,24.2245985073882));
#1632=CARTESIAN_POINT('',(1.57445963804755,7.16764270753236,24.5435350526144));
#1633=CARTESIAN_POINT('',(1.80961520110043,6.76204797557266,23.4489856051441));
#1634=CARTESIAN_POINT('',(1.92455575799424,6.73061065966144,23.834215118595));
#1635=CARTESIAN_POINT('',(1.92566078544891,6.73030583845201,24.262703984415));
#1636=CARTESIAN_POINT('',(1.80954635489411,6.76206639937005,24.6512472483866));
#1637=B_SPLINE_SURFACE_WITH_KNOTS('',1,3,((#1629,#1630,#1631,#1632),(#1633,#1634,#1635,#1636)),
.UNSPECIFIED.,.F.,.F.,.F.,(2,2),(4,4),(0.,1.),(0.00592011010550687,0.00713496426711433),.UNSPECIFIED.);
#1638=CARTESIAN_POINT('',(1.58999669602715,7.1593098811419,23.5996069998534));
#1639=CARTESIAN_POINT('',(1.60014265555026,7.14247139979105,23.5968608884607));
#1640=CARTESIAN_POINT('',(1.61029556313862,7.12563138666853,23.5941498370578));
#1641=CARTESIAN_POINT('',(1.63061156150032,7.09195414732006,23.5887989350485));
#1642=CARTESIAN_POINT('',(1.64077464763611,7.07511692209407,23.5861590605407));
#1643=CARTESIAN_POINT('',(1.66111082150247,7.04144523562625,23.5809505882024));
#1644=CARTESIAN_POINT('',(1.67128390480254,7.02461077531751,23.5783819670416));
#1645=CARTESIAN_POINT('',(1.69163989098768,6.9909445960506,23.5733160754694));
#1646=CARTESIAN_POINT('',(1.70182278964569,6.97411287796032,23.5708187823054));
#1647=CARTESIAN_POINT('',(1.72219822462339,6.94045216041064,23.5658956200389));
#1648=CARTESIAN_POINT('',(1.73239075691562,6.92362316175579,23.5634697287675));
#1649=CARTESIAN_POINT('',(1.75278527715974,6.88996786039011,23.558689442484));
#1650=CARTESIAN_POINT('',(1.76298726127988,6.87314155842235,23.556335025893));
#1651=CARTESIAN_POINT('',(1.78340050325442,6.8394916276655,23.5516977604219));
#1652=CARTESIAN_POINT('',(1.79361175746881,6.82266799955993,23.5494148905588));
#1653=CARTESIAN_POINT('',(1.81404335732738,6.78902339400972,23.5449207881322));
#1654=CARTESIAN_POINT('',(1.82426369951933,6.77220241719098,23.5427095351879));
#1655=CARTESIAN_POINT('',(1.83448991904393,6.75538041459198,23.5405338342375));
#1656=B_SPLINE_CURVE_WITH_KNOTS('',3,(#1638,#1639,#1640,#1641,#1642,#1643,#1644,#1645,#1646,
#1647,#1648,#1649,#1650,#1651,#1652,#1653,#1654,#1655),.UNSPECIFIED.,.F.,.F.,(4,2,2,2,2,2,2,2,
4),(0.,0.0595494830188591,0.119078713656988,0.178588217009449,0.238078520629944,
0.297550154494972,0.357003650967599,0.416439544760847,0.475858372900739),.UNSPECIFIED.);
#1657=EDGE_CURVE('E635',#995,#1164,#1656,.F.);
#1658=ORIENTED_EDGE('',*,*,#1623,.T.);
#1659=ORIENTED_EDGE('',*,*,#1174,.F.);
#1660=ORIENTED_EDGE('',*,*,#1657,.F.);
#1661=ORIENTED_EDGE('',*,*,#996,.F.);
#1662=EDGE_LOOP('',(#1658,#1659,#1660,#1661));
#1663=FACE_BOUND('',#1662,.T.);
#1664=ADVANCED_FACE('F639',(#1663),#1637,.T.);
#1665=CARTESIAN_POINT('',(1.5875,7.15221357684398,30.4));
#1666=DIRECTION('',(-0.849044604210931,-0.528321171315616,0.));
#1667=DIRECTION('',(0.528321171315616,-0.849044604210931,0.));
#1668=AXIS2_PLACEMENT_3D('',#1665,#1666,#1667);
#1669=PLANE('',#1668);
#1670=ORIENTED_EDGE('',*,*,#1657,.T.);
#1671=ORIENTED_EDGE('',*,*,#1547,.F.);
#1672=CARTESIAN_POINT('',(1.83444761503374,6.75535357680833,21.5));
#1673=CARTESIAN_POINT('',(1.5875,7.15221357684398,21.5));
#1674=B_SPLINE_CURVE_WITH_KNOTS('',1,(#1672,#1673),.UNSPECIFIED.,.F.,.F.,(2,2),(0.,1.),.UNSPECIFIED.);
#1675=EDGE_CURVE('E758',#1003,#1540,#1674,.T.);
#1676=ORIENTED_EDGE('',*,*,#1675,.F.);
#1677=ORIENTED_EDGE('',*,*,#1004,.F.);
#1678=EDGE_LOOP('',(#1670,#1671,#1676,#1677));
#1679=FACE_BOUND('',#1678,.T.);
#1680=ADVANCED_FACE('F661',(#1679),#1669,.T.);
#1681=CARTESIAN_POINT('',(-1.5875,7.15221357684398,21.5));
#1682=CARTESIAN_POINT('',(-1.58873442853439,7.15059829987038,21.0777889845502));
#1683=CARTESIAN_POINT('',(-1.4150351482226,7.2142268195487,20.6700099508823));
#1684=CARTESIAN_POINT('',(-0.829134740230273,7.35172857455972,20.084032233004));
#1685=CARTESIAN_POINT('',(-0.416867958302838,7.4112761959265,19.9124299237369));
#1686=CARTESIAN_POINT('',(0.419761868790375,7.41118810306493,19.9125713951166));
#1687=CARTESIAN_POINT('',(0.83032639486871,7.35159016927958,20.0849177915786));
#1688=CARTESIAN_POINT('',(1.41479420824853,7.21414592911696,20.6700747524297));
#1689=CARTESIAN_POINT('',(1.58902400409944,7.15047343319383,21.0814565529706));
#1690=CARTESIAN_POINT('',(1.5875,7.15221357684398,21.5));
#1691=CARTESIAN_POINT('',(-1.83444761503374,6.75535357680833,21.5));
#1692=CARTESIAN_POINT('',(-1.83587406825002,6.75382792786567,20.9834486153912));
#1693=CARTESIAN_POINT('',(-1.63515455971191,6.81392584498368,20.4845539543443));
#1694=CARTESIAN_POINT('',(-0.958112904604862,6.94379794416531,19.7676432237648));
#1695=CARTESIAN_POINT('',(-0.481714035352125,7.00004140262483,19.5576974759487));
#1696=CARTESIAN_POINT('',(0.48505811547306,6.99995819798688,19.5578705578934));
#1697=CARTESIAN_POINT('',(0.959489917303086,6.94366722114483,19.7687266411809));
#1698=CARTESIAN_POINT('',(1.63487615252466,6.81384944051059,20.4846332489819));
#1699=CARTESIAN_POINT('',(1.83620868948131,6.75370998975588,20.9879356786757));
#1700=CARTESIAN_POINT('',(1.83444761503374,6.75535357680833,21.5));
#1701=B_SPLINE_SURFACE_WITH_KNOTS('',1,3,((#1681,#1682,#1683,#1684,#1685,#1686,#1687,#1688,
#1689,#1690),(#1691,#1692,#1693,#1694,#1695,#1696,#1697,#1698,#1699,#1700)),.UNSPECIFIED.,.F.,
.F.,.F.,(2,2),(4,2,2,2,4),(0.,1.),(0.,0.00152425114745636,0.00304850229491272,
0.00457275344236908,0.00609700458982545),.UNSPECIFIED.);
#1702=CARTESIAN_POINT('',(-1.5875,7.15221357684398,21.5));
#1703=CARTESIAN_POINT('',(-1.59778948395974,7.13567774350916,21.5));
#1704=CARTESIAN_POINT('',(-1.60807896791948,7.11914191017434,21.5));
#1705=CARTESIAN_POINT('',(-1.62865793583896,7.08607024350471,21.5));
#1706=CARTESIAN_POINT('',(-1.63894741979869,7.06953441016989,21.5));
#1707=CARTESIAN_POINT('',(-1.65952638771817,7.03646274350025,21.5));
#1708=CARTESIAN_POINT('',(-1.66981587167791,7.01992691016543,21.5));
#1709=CARTESIAN_POINT('',(-1.69039483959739,6.98685524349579,21.5));
#1710=CARTESIAN_POINT('',(-1.70068432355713,6.97031941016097,21.5));
#1711=CARTESIAN_POINT('',(-1.72126329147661,6.93724774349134,21.5));
#1712=CARTESIAN_POINT('',(-1.73155277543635,6.92071191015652,21.5));
#1713=CARTESIAN_POINT('',(-1.75213174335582,6.88764024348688,21.5));
#1714=CARTESIAN_POINT('',(-1.76242122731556,6.87110441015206,21.5));
#1715=CARTESIAN_POINT('',(-1.78300019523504,6.83803274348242,21.5));
#1716=CARTESIAN_POINT('',(-1.79328967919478,6.8214969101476,21.5));
#1717=CARTESIAN_POINT('',(-1.81386864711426,6.78842524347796,21.5));
#1718=CARTESIAN_POINT('',(-1.824158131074,6.77188941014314,21.5));
#1719=CARTESIAN_POINT('',(-1.83444761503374,6.75535357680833,21.5));
#1720=B_SPLINE_CURVE_WITH_KNOTS('',3,(#1702,#1703,#1704,#1705,#1706,#1707,#1708,#1709,#1710,
#1711,#1712,#1713,#1714,#1715,#1716,#1717,#1718,#1719),.UNSPECIFIED.,.F.,.F.,(4,2,2,2,2,2,2,2,
4),(0.,0.0584274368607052,0.116854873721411,0.175282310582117,0.233709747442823,
0.292137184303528,0.350564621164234,0.40899205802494,0.467419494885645),.UNSPECIFIED.);
#1721=EDGE_CURVE('E736',#1018,#1560,#1720,.F.);
#1722=ORIENTED_EDGE('',*,*,#1675,.T.);
#1723=ORIENTED_EDGE('',*,*,#1590,.F.);
#1724=ORIENTED_EDGE('',*,*,#1721,.F.);
#1725=ORIENTED_EDGE('',*,*,#1019,.F.);
#1726=EDGE_LOOP('',(#1722,#1723,#1724,#1725));
#1727=FACE_BOUND('',#1726,.T.);
#1728=ADVANCED_FACE('F713',(#1727),#1701,.T.);
#1729=CARTESIAN_POINT('',(-1.5875,7.15221357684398,30.4));
#1730=DIRECTION('',(-0.84904460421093,0.528321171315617,0.));
#1731=DIRECTION('',(-0.528321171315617,-0.84904460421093,0.));
#1732=AXIS2_PLACEMENT_3D('',#1729,#1730,#1731);
#1733=PLANE('',#1732);
#1734=ORIENTED_EDGE('',*,*,#1721,.T.);
#1735=ORIENTED_EDGE('',*,*,#1561,.F.);
#1736=CARTESIAN_POINT('',(-1.83458309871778,6.75521802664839,23.5404997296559));
#1737=CARTESIAN_POINT('',(-1.82435298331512,6.77204673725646,23.5426773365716));
#1738=CARTESIAN_POINT('',(-1.8141287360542,6.78887442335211,23.5448904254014));
#1739=CARTESIAN_POINT('',(-1.79368930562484,6.82253245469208,23.5493880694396));
#1740=CARTESIAN_POINT('',(-1.78347412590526,6.83936279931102,23.5516726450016));
#1741=CARTESIAN_POINT('',(-1.76305301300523,6.87302617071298,23.5563132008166));
#1742=CARTESIAN_POINT('',(-1.75284708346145,6.88985919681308,23.5586692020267));
#1743=CARTESIAN_POINT('',(-1.73244465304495,6.92352795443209,23.5634525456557));
#1744=CARTESIAN_POINT('',(-1.72224815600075,6.94036368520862,23.5658799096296));
#1745=CARTESIAN_POINT('',(-1.7018647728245,6.97403787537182,23.5708059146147));
#1746=CARTESIAN_POINT('',(-1.69167789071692,6.9908763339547,23.5733045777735));
#1747=CARTESIAN_POINT('',(-1.67131391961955,7.02455600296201,23.5783731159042));
#1748=CARTESIAN_POINT('',(-1.66113683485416,7.04139721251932,23.5809430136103));
#1749=CARTESIAN_POINT('',(-1.64079264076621,7.07508240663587,23.58615395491));
#1750=CARTESIAN_POINT('',(-1.63062553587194,7.09192639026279,23.5887950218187));
#1751=CARTESIAN_POINT('',(-1.61030148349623,7.12561715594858,23.5941482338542));
#1752=CARTESIAN_POINT('',(-1.60014454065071,7.14246393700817,23.596860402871));
#1753=CARTESIAN_POINT('',(-1.58999453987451,7.15930918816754,23.5996075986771));
#1754=B_SPLINE_CURVE_WITH_KNOTS('',3,(#1736,#1737,#1738,#1739,#1740,#1741,#1742,#1743,#1744,
#1745,#1746,#1747,#1748,#1749,#1750,#1751,#1752,#1753),.UNSPECIFIED.,.F.,.F.,(4,2,2,2,2,2,2,2,
4),(0.,0.0594425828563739,0.11890224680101,0.178379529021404,0.237874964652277,0.29738908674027,
0.356922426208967,0.416475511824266,0.476048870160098),.UNSPECIFIED.);
#1755=EDGE_CURVE('E776',#959,#1139,#1754,.T.);
#1756=ORIENTED_EDGE('',*,*,#1755,.F.);
#1757=ORIENTED_EDGE('',*,*,#1025,.F.);
#1758=EDGE_LOOP('',(#1734,#1735,#1756,#1757));
#1759=FACE_BOUND('',#1758,.T.);
#1760=ADVANCED_FACE('F704',(#1759),#1733,.F.);
#1761=CARTESIAN_POINT('',(-1.5744623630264,7.16764181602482,24.5435263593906));
#1762=CARTESIAN_POINT('',(-1.67473582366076,7.13423053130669,24.2265667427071));
#1763=CARTESIAN_POINT('',(-1.67535056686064,7.13402442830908,23.8753324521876));
#1764=CARTESIAN_POINT('',(-1.57439277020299,7.16766450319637,23.5562516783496));
#1765=CARTESIAN_POINT('',(-1.80954948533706,6.76206556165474,24.651236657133));
#1766=CARTESIAN_POINT('',(-1.92479504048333,6.73054483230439,24.2651017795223));
#1767=CARTESIAN_POINT('',(-1.92550157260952,6.73035039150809,23.8372119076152));
#1768=CARTESIAN_POINT('',(-1.8094695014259,6.76208696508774,23.4484929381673));
#1769=B_SPLINE_SURFACE_WITH_KNOTS('',1,3,((#1761,#1762,#1763,#1764),(#1765,#1766,#1767,#1768)),
.UNSPECIFIED.,.F.,.F.,.F.,(2,2),(4,4),(0.,1.),(0.00598488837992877,0.00720026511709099),.UNSPECIFIED.);
#1770=CARTESIAN_POINT('',(-1.58999700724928,7.15930964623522,24.5003931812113));
#1771=CARTESIAN_POINT('',(-1.60014302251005,7.14247119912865,24.5031391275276));
#1772=CARTESIAN_POINT('',(-1.61029598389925,7.12563122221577,24.5058500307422));
#1773=CARTESIAN_POINT('',(-1.6306120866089,7.09195405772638,24.511200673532));
#1774=CARTESIAN_POINT('',(-1.64077522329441,7.07511687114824,24.51384043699));
#1775=CARTESIAN_POINT('',(-1.66111149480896,7.04144526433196,24.5190487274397));
#1776=CARTESIAN_POINT('',(-1.67128462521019,7.02461084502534,24.521617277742));
#1777=CARTESIAN_POINT('',(-1.69164070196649,6.99094475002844,24.5266830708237));
#1778=CARTESIAN_POINT('',(-1.70182364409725,6.97411307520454,24.5291803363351));
#1779=CARTESIAN_POINT('',(-1.72219916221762,6.94045244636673,24.5341034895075));
#1780=CARTESIAN_POINT('',(-1.73239173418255,6.9236234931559,24.536529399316));
#1781=CARTESIAN_POINT('',(-1.75278632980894,6.88996828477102,24.5413097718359));
#1782=CARTESIAN_POINT('',(-1.76298834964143,6.87314203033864,24.5436642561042));
#1783=CARTESIAN_POINT('',(-1.78340165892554,6.83949219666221,24.5483017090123));
#1784=CARTESIAN_POINT('',(-1.79361294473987,6.82266861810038,24.5505846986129));
#1785=CARTESIAN_POINT('',(-1.81404460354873,6.78902411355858,24.5550790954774));
#1786=CARTESIAN_POINT('',(-1.82426497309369,6.77220318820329,24.5572905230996));
#1787=CARTESIAN_POINT('',(-1.83449121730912,6.75538123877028,24.5594664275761));
#1788=B_SPLINE_CURVE_WITH_KNOTS('',3,(#1770,#1771,#1772,#1773,#1774,#1775,#1776,#1777,#1778,
#1779,#1780,#1781,#1782,#1783,#1784,#1785,#1786,#1787),.UNSPECIFIED.,.F.,.F.,(4,2,2,2,2,2,2,2,
4),(0.,0.0595494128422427,0.119078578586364,0.178588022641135,0.238078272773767,
0.297549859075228,0.357003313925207,0.416439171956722,0.475857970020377),.UNSPECIFIED.);
#1789=EDGE_CURVE('E568',#961,#1130,#1788,.F.);
#1790=ORIENTED_EDGE('',*,*,#1755,.T.);
#1791=ORIENTED_EDGE('',*,*,#1140,.F.);
#1792=ORIENTED_EDGE('',*,*,#1789,.F.);
#1793=ORIENTED_EDGE('',*,*,#962,.F.);
#1794=EDGE_LOOP('',(#1790,#1791,#1792,#1793));
#1795=FACE_BOUND('',#1794,.T.);
#1796=ADVANCED_FACE('F712',(#1795),#1769,.T.);
#1797=CARTESIAN_POINT('',(-1.5875,7.15221357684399,30.4));
#1798=DIRECTION('',(-0.849044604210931,0.528321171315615,0.));
#1799=DIRECTION('',(-0.528321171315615,-0.849044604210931,0.));
#1800=AXIS2_PLACEMENT_3D('',#1797,#1798,#1799);
#1801=PLANE('',#1800);
#1802=ORIENTED_EDGE('',*,*,#1219,.F.);
#1803=ORIENTED_EDGE('',*,*,#970,.F.);
#1804=ORIENTED_EDGE('',*,*,#1789,.T.);
#1805=ORIENTED_EDGE('',*,*,#1491,.F.);
#1806=EDGE_LOOP('',(#1802,#1803,#1804,#1805));
#1807=FACE_BOUND('',#1806,.T.);
#1808=ADVANCED_FACE('F220',(#1807),#1801,.F.);
#1809=CLOSED_SHELL('',(#134,#162,#190,#218,#246,#274,#302,#330,#358,#378,#401,#445,#457,#477,
#489,#509,#521,#541,#553,#573,#585,#605,#617,#637,#649,#669,#681,#701,#713,#765,#947,#1117,
#1191,#1203,#1457,#1480,#1503,#1515,#1534,#1553,#1572,#1596,#1628,#1664,#1680,#1728,#1760,#1796,#1808));
#1810=MANIFOLD_SOLID_BREP('B2',#1809);
#1811=ADVANCED_BREP_SHAPE_REPRESENTATION('',(#18,#1810),#14);
#1812=SHAPE_DEFINITION_REPRESENTATION(#9,#1811);
ENDSEC;
END-ISO-10303-21;
